VERSION 5.8 ;
BUSBITCHARS "[]" ;
DIVIDERCHAR "/" ;
UNITS
    DATABASE MICRONS 1000 ;
END UNITS

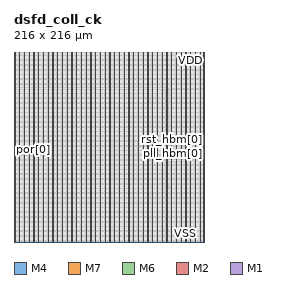
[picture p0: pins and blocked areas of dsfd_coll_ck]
MACRO dsfd_coll_ck
  FOREIGN dsfd_coll_ck 0 0 ;
  CLASS BLOCK ;
  SIZE 216 BY 216 ;
  PIN pll_hbm[0]
    DIRECTION OUTPUT ;
    USE SIGNAL ;
    PORT
      LAYER M4 ;
        RECT  215.808 100.8 216 100.824 ;
    END
  END pll_hbm[0]
  PIN pll_serial[0]
    DIRECTION OUTPUT ;
    USE SIGNAL ;
    PORT
      LAYER M4 ;
        RECT  215.808 98.4 216 98.424 ;
    END
  END pll_serial[0]
  PIN pll_stream[0]
    DIRECTION OUTPUT ;
    USE SIGNAL ;
    PORT
      LAYER M4 ;
        RECT  215.808 96 216 96.024 ;
    END
  END pll_stream[0]
  PIN por[0]
    DIRECTION INPUT ;
    USE SIGNAL ;
    PORT
      LAYER M4 ;
        RECT  0 105.6 0.192 105.624 ;
    END
  END por[0]
  PIN refclk[0]
    DIRECTION INPUT ;
    USE SIGNAL ;
    PORT
      LAYER M4 ;
        RECT  0 100.8 0.192 100.824 ;
    END
  END refclk[0]
  PIN rst_hbm[0]
    DIRECTION OUTPUT ;
    USE SIGNAL ;
    PORT
      LAYER M4 ;
        RECT  215.808 108 216 108.024 ;
    END
  END rst_hbm[0]
  PIN rst_serial[0]
    DIRECTION OUTPUT ;
    USE SIGNAL ;
    PORT
      LAYER M4 ;
        RECT  215.808 105.6 216 105.624 ;
    END
  END rst_serial[0]
  PIN rst_stream[0]
    DIRECTION OUTPUT ;
    USE SIGNAL ;
    PORT
      LAYER M4 ;
        RECT  215.808 103.2 216 103.224 ;
    END
  END rst_stream[0]
  PIN VDD
    DIRECTION INOUT ;
    USE POWER ;
    PORT
      LAYER M7 ;
        RECT  211.456 0.531 211.744 215.469 ;
        RECT  200.656 0.531 200.944 215.469 ;
        RECT  189.856 0.531 190.144 215.469 ;
        RECT  179.056 0.531 179.344 215.469 ;
        RECT  168.256 0.531 168.544 215.469 ;
        RECT  157.456 0.531 157.744 215.469 ;
        RECT  146.656 0.531 146.944 215.469 ;
        RECT  135.856 0.531 136.144 215.469 ;
        RECT  125.056 0.531 125.344 215.469 ;
        RECT  114.256 0.531 114.544 215.469 ;
        RECT  103.456 0.531 103.744 215.469 ;
        RECT  92.656 0.531 92.944 215.469 ;
        RECT  81.856 0.531 82.144 215.469 ;
        RECT  71.056 0.531 71.344 215.469 ;
        RECT  60.256 0.531 60.544 215.469 ;
        RECT  49.456 0.531 49.744 215.469 ;
        RECT  38.656 0.531 38.944 215.469 ;
        RECT  27.856 0.531 28.144 215.469 ;
        RECT  17.056 0.531 17.344 215.469 ;
        RECT  6.256 0.531 6.544 215.469 ;
      LAYER M6 ;
        RECT  215.968 212.172 216 212.46 ;
        RECT  0 212.172 0.032 212.46 ;
        RECT  215.968 206.772 216 207.06 ;
        RECT  0 206.772 0.032 207.06 ;
        RECT  215.968 201.372 216 201.66 ;
        RECT  0 201.372 0.032 201.66 ;
        RECT  215.968 195.972 216 196.26 ;
        RECT  0 195.972 0.032 196.26 ;
        RECT  215.968 190.572 216 190.86 ;
        RECT  0 190.572 0.032 190.86 ;
        RECT  215.968 185.172 216 185.46 ;
        RECT  0 185.172 0.032 185.46 ;
        RECT  215.968 179.772 216 180.06 ;
        RECT  0 179.772 0.032 180.06 ;
        RECT  215.968 174.372 216 174.66 ;
        RECT  0 174.372 0.032 174.66 ;
        RECT  215.968 168.972 216 169.26 ;
        RECT  0 168.972 0.032 169.26 ;
        RECT  215.968 163.572 216 163.86 ;
        RECT  0 163.572 0.032 163.86 ;
        RECT  215.968 158.172 216 158.46 ;
        RECT  0 158.172 0.032 158.46 ;
        RECT  215.968 152.772 216 153.06 ;
        RECT  0 152.772 0.032 153.06 ;
        RECT  215.968 147.372 216 147.66 ;
        RECT  0 147.372 0.032 147.66 ;
        RECT  215.968 141.972 216 142.26 ;
        RECT  0 141.972 0.032 142.26 ;
        RECT  215.968 136.572 216 136.86 ;
        RECT  0 136.572 0.032 136.86 ;
        RECT  215.968 131.172 216 131.46 ;
        RECT  0 131.172 0.032 131.46 ;
        RECT  215.968 125.772 216 126.06 ;
        RECT  0 125.772 0.032 126.06 ;
        RECT  215.968 120.372 216 120.66 ;
        RECT  0 120.372 0.032 120.66 ;
        RECT  215.968 114.972 216 115.26 ;
        RECT  0 114.972 0.032 115.26 ;
        RECT  215.968 109.572 216 109.86 ;
        RECT  0 109.572 0.032 109.86 ;
        RECT  215.968 104.172 216 104.46 ;
        RECT  0 104.172 0.032 104.46 ;
        RECT  215.968 98.772 216 99.06 ;
        RECT  0 98.772 0.032 99.06 ;
        RECT  215.968 93.372 216 93.66 ;
        RECT  0 93.372 0.032 93.66 ;
        RECT  215.968 87.972 216 88.26 ;
        RECT  0 87.972 0.032 88.26 ;
        RECT  215.968 82.572 216 82.86 ;
        RECT  0 82.572 0.032 82.86 ;
        RECT  215.968 77.172 216 77.46 ;
        RECT  0 77.172 0.032 77.46 ;
        RECT  215.968 71.772 216 72.06 ;
        RECT  0 71.772 0.032 72.06 ;
        RECT  215.968 66.372 216 66.66 ;
        RECT  0 66.372 0.032 66.66 ;
        RECT  215.968 60.972 216 61.26 ;
        RECT  0 60.972 0.032 61.26 ;
        RECT  215.968 55.572 216 55.86 ;
        RECT  0 55.572 0.032 55.86 ;
        RECT  215.968 50.172 216 50.46 ;
        RECT  0 50.172 0.032 50.46 ;
        RECT  215.968 44.772 216 45.06 ;
        RECT  0 44.772 0.032 45.06 ;
        RECT  215.968 39.372 216 39.66 ;
        RECT  0 39.372 0.032 39.66 ;
        RECT  215.968 33.972 216 34.26 ;
        RECT  0 33.972 0.032 34.26 ;
        RECT  215.968 28.572 216 28.86 ;
        RECT  0 28.572 0.032 28.86 ;
        RECT  215.968 23.172 216 23.46 ;
        RECT  0 23.172 0.032 23.46 ;
        RECT  215.968 17.772 216 18.06 ;
        RECT  0 17.772 0.032 18.06 ;
        RECT  215.968 12.372 216 12.66 ;
        RECT  0 12.372 0.032 12.66 ;
        RECT  215.968 6.972 216 7.26 ;
        RECT  0 6.972 0.032 7.26 ;
        RECT  215.968 1.572 216 1.86 ;
        RECT  0 1.572 0.032 1.86 ;
      LAYER M2 ;
        RECT  215.982 175.221 216 175.239 ;
        RECT  215.982 174.681 216 174.699 ;
        RECT  215.982 174.141 216 174.159 ;
        RECT  215.982 173.601 216 173.619 ;
        RECT  215.982 173.061 216 173.079 ;
        RECT  215.982 172.521 216 172.539 ;
        RECT  215.982 171.981 216 171.999 ;
        RECT  215.982 171.441 216 171.459 ;
        RECT  215.982 170.901 216 170.919 ;
        RECT  215.982 170.361 216 170.379 ;
        RECT  215.982 169.821 216 169.839 ;
        RECT  215.982 169.281 216 169.299 ;
        RECT  215.982 168.741 216 168.759 ;
        RECT  215.982 168.201 216 168.219 ;
        RECT  215.982 167.661 216 167.679 ;
        RECT  215.982 167.121 216 167.139 ;
        RECT  215.982 166.581 216 166.599 ;
        RECT  215.982 166.041 216 166.059 ;
        RECT  215.982 165.501 216 165.519 ;
        RECT  215.982 164.961 216 164.979 ;
        RECT  215.982 164.421 216 164.439 ;
        RECT  215.982 163.881 216 163.899 ;
        RECT  215.982 163.341 216 163.359 ;
        RECT  215.982 162.801 216 162.819 ;
        RECT  215.982 162.261 216 162.279 ;
        RECT  215.982 161.721 216 161.739 ;
        RECT  215.982 161.181 216 161.199 ;
        RECT  215.982 160.641 216 160.659 ;
        RECT  215.982 160.101 216 160.119 ;
        RECT  215.982 159.561 216 159.579 ;
        RECT  215.982 159.021 216 159.039 ;
        RECT  215.982 158.481 216 158.499 ;
        RECT  215.982 157.941 216 157.959 ;
        RECT  215.982 157.401 216 157.419 ;
        RECT  215.982 156.861 216 156.879 ;
        RECT  215.982 156.321 216 156.339 ;
        RECT  215.982 155.781 216 155.799 ;
        RECT  215.982 155.241 216 155.259 ;
        RECT  215.982 154.701 216 154.719 ;
        RECT  215.982 154.161 216 154.179 ;
        RECT  215.982 153.621 216 153.639 ;
        RECT  215.982 153.081 216 153.099 ;
        RECT  215.982 152.541 216 152.559 ;
        RECT  215.982 152.001 216 152.019 ;
        RECT  215.982 151.461 216 151.479 ;
        RECT  215.982 150.921 216 150.939 ;
        RECT  215.982 150.381 216 150.399 ;
        RECT  215.982 149.841 216 149.859 ;
        RECT  215.982 149.301 216 149.319 ;
        RECT  215.982 148.761 216 148.779 ;
        RECT  215.982 148.221 216 148.239 ;
        RECT  215.982 147.681 216 147.699 ;
        RECT  215.982 147.141 216 147.159 ;
        RECT  215.982 146.601 216 146.619 ;
        RECT  215.982 146.061 216 146.079 ;
        RECT  215.982 145.521 216 145.539 ;
        RECT  215.982 144.981 216 144.999 ;
        RECT  215.982 144.441 216 144.459 ;
        RECT  215.982 143.901 216 143.919 ;
        RECT  215.982 143.361 216 143.379 ;
        RECT  215.982 142.821 216 142.839 ;
        RECT  215.982 142.281 216 142.299 ;
        RECT  215.982 141.741 216 141.759 ;
        RECT  215.982 141.201 216 141.219 ;
        RECT  215.982 140.661 216 140.679 ;
        RECT  215.982 140.121 216 140.139 ;
        RECT  215.982 139.581 216 139.599 ;
        RECT  215.982 139.041 216 139.059 ;
        RECT  215.982 138.501 216 138.519 ;
        RECT  215.982 137.961 216 137.979 ;
        RECT  215.982 137.421 216 137.439 ;
        RECT  215.982 136.881 216 136.899 ;
        RECT  215.982 136.341 216 136.359 ;
        RECT  215.982 135.801 216 135.819 ;
        RECT  215.982 135.261 216 135.279 ;
        RECT  215.982 134.721 216 134.739 ;
        RECT  215.982 134.181 216 134.199 ;
        RECT  215.982 133.641 216 133.659 ;
        RECT  215.982 133.101 216 133.119 ;
        RECT  215.982 132.561 216 132.579 ;
        RECT  215.982 132.021 216 132.039 ;
        RECT  215.982 131.481 216 131.499 ;
        RECT  215.982 130.941 216 130.959 ;
        RECT  215.982 130.401 216 130.419 ;
        RECT  215.982 129.861 216 129.879 ;
        RECT  215.982 129.321 216 129.339 ;
        RECT  215.982 128.781 216 128.799 ;
        RECT  215.982 128.241 216 128.259 ;
        RECT  215.982 127.701 216 127.719 ;
        RECT  215.982 127.161 216 127.179 ;
        RECT  215.982 126.621 216 126.639 ;
        RECT  215.982 126.081 216 126.099 ;
        RECT  215.982 125.541 216 125.559 ;
        RECT  215.982 125.001 216 125.019 ;
        RECT  215.982 124.461 216 124.479 ;
        RECT  215.982 123.921 216 123.939 ;
        RECT  215.982 123.381 216 123.399 ;
        RECT  215.982 122.841 216 122.859 ;
        RECT  215.982 122.301 216 122.319 ;
        RECT  215.982 121.761 216 121.779 ;
        RECT  215.982 121.221 216 121.239 ;
        RECT  215.982 120.681 216 120.699 ;
        RECT  215.982 120.141 216 120.159 ;
        RECT  215.982 119.601 216 119.619 ;
        RECT  215.982 119.061 216 119.079 ;
        RECT  215.982 118.521 216 118.539 ;
        RECT  215.982 117.981 216 117.999 ;
        RECT  215.982 117.441 216 117.459 ;
        RECT  215.982 116.901 216 116.919 ;
        RECT  215.982 116.361 216 116.379 ;
        RECT  215.982 115.821 216 115.839 ;
        RECT  215.982 115.281 216 115.299 ;
        RECT  215.982 114.741 216 114.759 ;
        RECT  215.982 114.201 216 114.219 ;
        RECT  215.982 113.661 216 113.679 ;
        RECT  215.982 113.121 216 113.139 ;
        RECT  215.982 112.581 216 112.599 ;
        RECT  215.982 112.041 216 112.059 ;
        RECT  215.982 111.501 216 111.519 ;
        RECT  215.982 110.961 216 110.979 ;
        RECT  215.982 110.421 216 110.439 ;
        RECT  215.982 109.881 216 109.899 ;
        RECT  215.982 109.341 216 109.359 ;
        RECT  215.982 108.801 216 108.819 ;
        RECT  215.982 108.261 216 108.279 ;
        RECT  215.982 107.721 216 107.739 ;
        RECT  215.982 107.181 216 107.199 ;
        RECT  215.982 106.641 216 106.659 ;
        RECT  215.982 106.101 216 106.119 ;
        RECT  215.982 105.561 216 105.579 ;
        RECT  215.982 105.021 216 105.039 ;
        RECT  215.982 104.481 216 104.499 ;
        RECT  215.982 103.941 216 103.959 ;
        RECT  215.982 103.401 216 103.419 ;
        RECT  215.982 102.861 216 102.879 ;
        RECT  215.982 102.321 216 102.339 ;
        RECT  215.982 101.781 216 101.799 ;
        RECT  215.982 101.241 216 101.259 ;
        RECT  215.982 100.701 216 100.719 ;
        RECT  215.982 100.161 216 100.179 ;
        RECT  215.982 99.621 216 99.639 ;
        RECT  215.982 99.081 216 99.099 ;
        RECT  215.982 98.541 216 98.559 ;
        RECT  215.982 98.001 216 98.019 ;
        RECT  215.982 97.461 216 97.479 ;
        RECT  215.982 96.921 216 96.939 ;
        RECT  215.982 96.381 216 96.399 ;
        RECT  215.982 95.841 216 95.859 ;
        RECT  215.982 95.301 216 95.319 ;
        RECT  215.982 94.761 216 94.779 ;
        RECT  215.982 94.221 216 94.239 ;
        RECT  215.982 93.681 216 93.699 ;
        RECT  215.982 93.141 216 93.159 ;
        RECT  215.982 92.601 216 92.619 ;
        RECT  215.982 92.061 216 92.079 ;
        RECT  215.982 91.521 216 91.539 ;
        RECT  215.982 90.981 216 90.999 ;
        RECT  215.982 90.441 216 90.459 ;
        RECT  215.982 89.901 216 89.919 ;
        RECT  215.982 89.361 216 89.379 ;
        RECT  215.982 88.821 216 88.839 ;
        RECT  215.982 88.281 216 88.299 ;
        RECT  215.982 87.741 216 87.759 ;
        RECT  215.982 87.201 216 87.219 ;
        RECT  215.982 86.661 216 86.679 ;
        RECT  215.982 86.121 216 86.139 ;
        RECT  215.982 85.581 216 85.599 ;
        RECT  215.982 85.041 216 85.059 ;
        RECT  215.982 84.501 216 84.519 ;
        RECT  215.982 83.961 216 83.979 ;
        RECT  215.982 83.421 216 83.439 ;
        RECT  215.982 82.881 216 82.899 ;
        RECT  215.982 82.341 216 82.359 ;
        RECT  215.982 81.801 216 81.819 ;
        RECT  215.982 81.261 216 81.279 ;
        RECT  215.982 80.721 216 80.739 ;
        RECT  215.982 80.181 216 80.199 ;
        RECT  215.982 79.641 216 79.659 ;
        RECT  215.982 79.101 216 79.119 ;
        RECT  215.982 78.561 216 78.579 ;
        RECT  215.982 78.021 216 78.039 ;
        RECT  215.982 77.481 216 77.499 ;
        RECT  215.982 76.941 216 76.959 ;
        RECT  215.982 76.401 216 76.419 ;
        RECT  215.982 75.861 216 75.879 ;
        RECT  215.982 75.321 216 75.339 ;
        RECT  215.982 74.781 216 74.799 ;
        RECT  215.982 74.241 216 74.259 ;
        RECT  215.982 73.701 216 73.719 ;
        RECT  215.982 73.161 216 73.179 ;
        RECT  215.982 72.621 216 72.639 ;
        RECT  215.982 72.081 216 72.099 ;
        RECT  215.982 71.541 216 71.559 ;
        RECT  215.982 71.001 216 71.019 ;
        RECT  215.982 70.461 216 70.479 ;
        RECT  215.982 69.921 216 69.939 ;
        RECT  215.982 69.381 216 69.399 ;
        RECT  215.982 68.841 216 68.859 ;
        RECT  215.982 68.301 216 68.319 ;
        RECT  215.982 67.761 216 67.779 ;
        RECT  215.982 67.221 216 67.239 ;
        RECT  215.982 66.681 216 66.699 ;
        RECT  215.982 66.141 216 66.159 ;
        RECT  215.982 65.601 216 65.619 ;
        RECT  215.982 65.061 216 65.079 ;
        RECT  215.982 64.521 216 64.539 ;
        RECT  215.982 63.981 216 63.999 ;
        RECT  215.982 63.441 216 63.459 ;
        RECT  215.982 62.901 216 62.919 ;
        RECT  215.982 62.361 216 62.379 ;
        RECT  215.982 61.821 216 61.839 ;
        RECT  215.982 61.281 216 61.299 ;
        RECT  215.982 60.741 216 60.759 ;
        RECT  215.982 60.201 216 60.219 ;
        RECT  215.982 59.661 216 59.679 ;
        RECT  215.982 59.121 216 59.139 ;
        RECT  215.982 58.581 216 58.599 ;
        RECT  215.982 58.041 216 58.059 ;
        RECT  215.982 57.501 216 57.519 ;
        RECT  215.982 56.961 216 56.979 ;
        RECT  215.982 56.421 216 56.439 ;
        RECT  215.982 55.881 216 55.899 ;
        RECT  215.982 55.341 216 55.359 ;
        RECT  215.982 54.801 216 54.819 ;
        RECT  215.982 54.261 216 54.279 ;
        RECT  215.982 53.721 216 53.739 ;
        RECT  215.982 53.181 216 53.199 ;
        RECT  215.982 52.641 216 52.659 ;
        RECT  215.982 52.101 216 52.119 ;
        RECT  215.982 51.561 216 51.579 ;
        RECT  215.982 51.021 216 51.039 ;
        RECT  215.982 50.481 216 50.499 ;
        RECT  215.982 49.941 216 49.959 ;
        RECT  215.982 49.401 216 49.419 ;
        RECT  215.982 48.861 216 48.879 ;
        RECT  215.982 48.321 216 48.339 ;
        RECT  215.982 47.781 216 47.799 ;
        RECT  215.982 47.241 216 47.259 ;
        RECT  215.982 46.701 216 46.719 ;
        RECT  215.982 46.161 216 46.179 ;
        RECT  215.982 45.621 216 45.639 ;
        RECT  215.982 45.081 216 45.099 ;
        RECT  215.982 44.541 216 44.559 ;
        RECT  215.982 44.001 216 44.019 ;
        RECT  215.982 43.461 216 43.479 ;
        RECT  215.982 42.921 216 42.939 ;
        RECT  215.982 42.381 216 42.399 ;
        RECT  215.982 41.841 216 41.859 ;
        RECT  215.982 41.301 216 41.319 ;
        RECT  215.982 40.761 216 40.779 ;
        RECT  215.982 40.221 216 40.239 ;
        RECT  215.982 39.681 216 39.699 ;
        RECT  215.982 39.141 216 39.159 ;
        RECT  215.982 38.601 216 38.619 ;
        RECT  215.982 38.061 216 38.079 ;
        RECT  215.982 37.521 216 37.539 ;
        RECT  215.982 36.981 216 36.999 ;
        RECT  215.982 36.441 216 36.459 ;
        RECT  215.982 35.901 216 35.919 ;
        RECT  215.982 35.361 216 35.379 ;
        RECT  215.982 34.821 216 34.839 ;
        RECT  215.982 34.281 216 34.299 ;
        RECT  215.982 33.741 216 33.759 ;
        RECT  215.982 33.201 216 33.219 ;
        RECT  215.982 32.661 216 32.679 ;
        RECT  215.982 32.121 216 32.139 ;
        RECT  215.982 31.581 216 31.599 ;
        RECT  215.982 31.041 216 31.059 ;
        RECT  215.982 30.501 216 30.519 ;
        RECT  215.982 29.961 216 29.979 ;
        RECT  215.982 29.421 216 29.439 ;
        RECT  215.982 28.881 216 28.899 ;
        RECT  215.982 28.341 216 28.359 ;
        RECT  215.982 27.801 216 27.819 ;
        RECT  215.982 27.261 216 27.279 ;
        RECT  215.982 26.721 216 26.739 ;
        RECT  215.982 26.181 216 26.199 ;
        RECT  215.982 25.641 216 25.659 ;
        RECT  215.982 25.101 216 25.119 ;
        RECT  215.982 24.561 216 24.579 ;
        RECT  215.982 24.021 216 24.039 ;
        RECT  215.982 23.481 216 23.499 ;
        RECT  215.982 22.941 216 22.959 ;
        RECT  215.982 22.401 216 22.419 ;
        RECT  215.982 21.861 216 21.879 ;
        RECT  215.982 21.321 216 21.339 ;
        RECT  215.982 20.781 216 20.799 ;
        RECT  215.982 20.241 216 20.259 ;
        RECT  215.982 19.701 216 19.719 ;
        RECT  215.982 19.161 216 19.179 ;
        RECT  215.982 18.621 216 18.639 ;
        RECT  215.982 18.081 216 18.099 ;
        RECT  215.982 17.541 216 17.559 ;
        RECT  215.982 17.001 216 17.019 ;
        RECT  215.982 16.461 216 16.479 ;
        RECT  215.982 15.921 216 15.939 ;
        RECT  215.982 15.381 216 15.399 ;
        RECT  215.982 14.841 216 14.859 ;
        RECT  215.982 14.301 216 14.319 ;
        RECT  215.982 13.761 216 13.779 ;
        RECT  215.982 13.221 216 13.239 ;
        RECT  215.982 12.681 216 12.699 ;
        RECT  215.982 12.141 216 12.159 ;
        RECT  215.982 11.601 216 11.619 ;
        RECT  215.982 11.061 216 11.079 ;
        RECT  215.982 10.521 216 10.539 ;
        RECT  215.982 9.981 216 9.999 ;
        RECT  215.982 9.441 216 9.459 ;
        RECT  215.982 8.901 216 8.919 ;
        RECT  215.982 8.361 216 8.379 ;
        RECT  215.982 7.821 216 7.839 ;
        RECT  215.982 7.281 216 7.299 ;
        RECT  215.982 6.741 216 6.759 ;
        RECT  215.982 6.201 216 6.219 ;
        RECT  215.982 5.661 216 5.679 ;
        RECT  215.982 5.121 216 5.139 ;
        RECT  215.982 4.581 216 4.599 ;
        RECT  215.982 4.041 216 4.059 ;
        RECT  215.982 3.501 216 3.519 ;
        RECT  215.982 2.961 216 2.979 ;
        RECT  215.982 2.421 216 2.439 ;
        RECT  215.982 1.881 216 1.899 ;
        RECT  215.982 1.341 216 1.359 ;
        RECT  215.982 0.801 216 0.819 ;
        RECT  215.982 215.181 216 215.199 ;
        RECT  0 215.181 0.018 215.199 ;
        RECT  215.982 214.641 216 214.659 ;
        RECT  0 214.641 0.018 214.659 ;
        RECT  215.982 214.101 216 214.119 ;
        RECT  0 214.101 0.018 214.119 ;
        RECT  215.982 213.561 216 213.579 ;
        RECT  0 213.561 0.018 213.579 ;
        RECT  215.982 213.021 216 213.039 ;
        RECT  0 213.021 0.018 213.039 ;
        RECT  215.982 212.481 216 212.499 ;
        RECT  0 212.481 0.018 212.499 ;
        RECT  215.982 211.941 216 211.959 ;
        RECT  0 211.941 0.018 211.959 ;
        RECT  215.982 211.401 216 211.419 ;
        RECT  0 211.401 0.018 211.419 ;
        RECT  215.982 210.861 216 210.879 ;
        RECT  0 210.861 0.018 210.879 ;
        RECT  215.982 210.321 216 210.339 ;
        RECT  0 210.321 0.018 210.339 ;
        RECT  215.982 209.781 216 209.799 ;
        RECT  0 209.781 0.018 209.799 ;
        RECT  215.982 209.241 216 209.259 ;
        RECT  0 209.241 0.018 209.259 ;
        RECT  215.982 208.701 216 208.719 ;
        RECT  0 208.701 0.018 208.719 ;
        RECT  215.982 208.161 216 208.179 ;
        RECT  0 208.161 0.018 208.179 ;
        RECT  215.982 207.621 216 207.639 ;
        RECT  0 207.621 0.018 207.639 ;
        RECT  215.982 207.081 216 207.099 ;
        RECT  0 207.081 0.018 207.099 ;
        RECT  215.982 206.541 216 206.559 ;
        RECT  0 206.541 0.018 206.559 ;
        RECT  215.982 206.001 216 206.019 ;
        RECT  0 206.001 0.018 206.019 ;
        RECT  215.982 205.461 216 205.479 ;
        RECT  0 205.461 0.018 205.479 ;
        RECT  215.982 204.921 216 204.939 ;
        RECT  0 204.921 0.018 204.939 ;
        RECT  215.982 204.381 216 204.399 ;
        RECT  0 204.381 0.018 204.399 ;
        RECT  215.982 203.841 216 203.859 ;
        RECT  0 203.841 0.018 203.859 ;
        RECT  215.982 203.301 216 203.319 ;
        RECT  0 203.301 0.018 203.319 ;
        RECT  215.982 202.761 216 202.779 ;
        RECT  0 202.761 0.018 202.779 ;
        RECT  215.982 202.221 216 202.239 ;
        RECT  0 202.221 0.018 202.239 ;
        RECT  215.982 201.681 216 201.699 ;
        RECT  0 201.681 0.018 201.699 ;
        RECT  215.982 201.141 216 201.159 ;
        RECT  0 201.141 0.018 201.159 ;
        RECT  215.982 200.601 216 200.619 ;
        RECT  0 200.601 0.018 200.619 ;
        RECT  215.982 200.061 216 200.079 ;
        RECT  0 200.061 0.018 200.079 ;
        RECT  215.982 199.521 216 199.539 ;
        RECT  0 199.521 0.018 199.539 ;
        RECT  215.982 198.981 216 198.999 ;
        RECT  0 198.981 0.018 198.999 ;
        RECT  215.982 198.441 216 198.459 ;
        RECT  0 198.441 0.018 198.459 ;
        RECT  215.982 197.901 216 197.919 ;
        RECT  0 197.901 0.018 197.919 ;
        RECT  215.982 197.361 216 197.379 ;
        RECT  0 197.361 0.018 197.379 ;
        RECT  215.982 196.821 216 196.839 ;
        RECT  0 196.821 0.018 196.839 ;
        RECT  215.982 196.281 216 196.299 ;
        RECT  0 196.281 0.018 196.299 ;
        RECT  215.982 195.741 216 195.759 ;
        RECT  0 195.741 0.018 195.759 ;
        RECT  215.982 195.201 216 195.219 ;
        RECT  0 195.201 0.018 195.219 ;
        RECT  215.982 194.661 216 194.679 ;
        RECT  0 194.661 0.018 194.679 ;
        RECT  215.982 194.121 216 194.139 ;
        RECT  0 194.121 0.018 194.139 ;
        RECT  215.982 193.581 216 193.599 ;
        RECT  0 193.581 0.018 193.599 ;
        RECT  215.982 193.041 216 193.059 ;
        RECT  0 193.041 0.018 193.059 ;
        RECT  215.982 192.501 216 192.519 ;
        RECT  0 192.501 0.018 192.519 ;
        RECT  215.982 191.961 216 191.979 ;
        RECT  0 191.961 0.018 191.979 ;
        RECT  215.982 191.421 216 191.439 ;
        RECT  0 191.421 0.018 191.439 ;
        RECT  215.982 190.881 216 190.899 ;
        RECT  0 190.881 0.018 190.899 ;
        RECT  215.982 190.341 216 190.359 ;
        RECT  0 190.341 0.018 190.359 ;
        RECT  215.982 189.801 216 189.819 ;
        RECT  0 189.801 0.018 189.819 ;
        RECT  215.982 189.261 216 189.279 ;
        RECT  0 189.261 0.018 189.279 ;
        RECT  215.982 188.721 216 188.739 ;
        RECT  0 188.721 0.018 188.739 ;
        RECT  215.982 188.181 216 188.199 ;
        RECT  0 188.181 0.018 188.199 ;
        RECT  215.982 187.641 216 187.659 ;
        RECT  0 187.641 0.018 187.659 ;
        RECT  215.982 187.101 216 187.119 ;
        RECT  0 187.101 0.018 187.119 ;
        RECT  215.982 186.561 216 186.579 ;
        RECT  0 186.561 0.018 186.579 ;
        RECT  215.982 186.021 216 186.039 ;
        RECT  0 186.021 0.018 186.039 ;
        RECT  215.982 185.481 216 185.499 ;
        RECT  0 185.481 0.018 185.499 ;
        RECT  215.982 184.941 216 184.959 ;
        RECT  0 184.941 0.018 184.959 ;
        RECT  215.982 184.401 216 184.419 ;
        RECT  0 184.401 0.018 184.419 ;
        RECT  215.982 183.861 216 183.879 ;
        RECT  0 183.861 0.018 183.879 ;
        RECT  215.982 183.321 216 183.339 ;
        RECT  0 183.321 0.018 183.339 ;
        RECT  215.982 182.781 216 182.799 ;
        RECT  0 182.781 0.018 182.799 ;
        RECT  215.982 182.241 216 182.259 ;
        RECT  0 182.241 0.018 182.259 ;
        RECT  215.982 181.701 216 181.719 ;
        RECT  0 181.701 0.018 181.719 ;
        RECT  215.982 181.161 216 181.179 ;
        RECT  0 181.161 0.018 181.179 ;
        RECT  215.982 180.621 216 180.639 ;
        RECT  0 180.621 0.018 180.639 ;
        RECT  215.982 180.081 216 180.099 ;
        RECT  0 180.081 0.018 180.099 ;
        RECT  215.982 179.541 216 179.559 ;
        RECT  0 179.541 0.018 179.559 ;
        RECT  215.982 179.001 216 179.019 ;
        RECT  0 179.001 0.018 179.019 ;
        RECT  215.982 178.461 216 178.479 ;
        RECT  0 178.461 0.018 178.479 ;
        RECT  215.982 177.921 216 177.939 ;
        RECT  0 177.921 0.018 177.939 ;
        RECT  215.982 177.381 216 177.399 ;
        RECT  0 177.381 0.018 177.399 ;
        RECT  215.982 176.841 216 176.859 ;
        RECT  0 176.841 0.018 176.859 ;
        RECT  215.982 176.301 216 176.319 ;
        RECT  0 176.301 0.018 176.319 ;
        RECT  215.982 175.761 216 175.779 ;
        RECT  0 175.761 0.018 175.779 ;
      LAYER M1 ;
        RECT  215.982 175.221 216 175.239 ;
        RECT  215.982 174.681 216 174.699 ;
        RECT  215.982 174.141 216 174.159 ;
        RECT  215.982 173.601 216 173.619 ;
        RECT  215.982 173.061 216 173.079 ;
        RECT  215.982 172.521 216 172.539 ;
        RECT  215.982 171.981 216 171.999 ;
        RECT  215.982 171.441 216 171.459 ;
        RECT  215.982 170.901 216 170.919 ;
        RECT  215.982 170.361 216 170.379 ;
        RECT  215.982 169.821 216 169.839 ;
        RECT  215.982 169.281 216 169.299 ;
        RECT  215.982 168.741 216 168.759 ;
        RECT  215.982 168.201 216 168.219 ;
        RECT  215.982 167.661 216 167.679 ;
        RECT  215.982 167.121 216 167.139 ;
        RECT  215.982 166.581 216 166.599 ;
        RECT  215.982 166.041 216 166.059 ;
        RECT  215.982 165.501 216 165.519 ;
        RECT  215.982 164.961 216 164.979 ;
        RECT  215.982 164.421 216 164.439 ;
        RECT  215.982 163.881 216 163.899 ;
        RECT  215.982 163.341 216 163.359 ;
        RECT  215.982 162.801 216 162.819 ;
        RECT  215.982 162.261 216 162.279 ;
        RECT  215.982 161.721 216 161.739 ;
        RECT  215.982 161.181 216 161.199 ;
        RECT  215.982 160.641 216 160.659 ;
        RECT  215.982 160.101 216 160.119 ;
        RECT  215.982 159.561 216 159.579 ;
        RECT  215.982 159.021 216 159.039 ;
        RECT  215.982 158.481 216 158.499 ;
        RECT  215.982 157.941 216 157.959 ;
        RECT  215.982 157.401 216 157.419 ;
        RECT  215.982 156.861 216 156.879 ;
        RECT  215.982 156.321 216 156.339 ;
        RECT  215.982 155.781 216 155.799 ;
        RECT  215.982 155.241 216 155.259 ;
        RECT  215.982 154.701 216 154.719 ;
        RECT  215.982 154.161 216 154.179 ;
        RECT  215.982 153.621 216 153.639 ;
        RECT  215.982 153.081 216 153.099 ;
        RECT  215.982 152.541 216 152.559 ;
        RECT  215.982 152.001 216 152.019 ;
        RECT  215.982 151.461 216 151.479 ;
        RECT  215.982 150.921 216 150.939 ;
        RECT  215.982 150.381 216 150.399 ;
        RECT  215.982 149.841 216 149.859 ;
        RECT  215.982 149.301 216 149.319 ;
        RECT  215.982 148.761 216 148.779 ;
        RECT  215.982 148.221 216 148.239 ;
        RECT  215.982 147.681 216 147.699 ;
        RECT  215.982 147.141 216 147.159 ;
        RECT  215.982 146.601 216 146.619 ;
        RECT  215.982 146.061 216 146.079 ;
        RECT  215.982 145.521 216 145.539 ;
        RECT  215.982 144.981 216 144.999 ;
        RECT  215.982 144.441 216 144.459 ;
        RECT  215.982 143.901 216 143.919 ;
        RECT  215.982 143.361 216 143.379 ;
        RECT  215.982 142.821 216 142.839 ;
        RECT  215.982 142.281 216 142.299 ;
        RECT  215.982 141.741 216 141.759 ;
        RECT  215.982 141.201 216 141.219 ;
        RECT  215.982 140.661 216 140.679 ;
        RECT  215.982 140.121 216 140.139 ;
        RECT  215.982 139.581 216 139.599 ;
        RECT  215.982 139.041 216 139.059 ;
        RECT  215.982 138.501 216 138.519 ;
        RECT  215.982 137.961 216 137.979 ;
        RECT  215.982 137.421 216 137.439 ;
        RECT  215.982 136.881 216 136.899 ;
        RECT  215.982 136.341 216 136.359 ;
        RECT  215.982 135.801 216 135.819 ;
        RECT  215.982 135.261 216 135.279 ;
        RECT  215.982 134.721 216 134.739 ;
        RECT  215.982 134.181 216 134.199 ;
        RECT  215.982 133.641 216 133.659 ;
        RECT  215.982 133.101 216 133.119 ;
        RECT  215.982 132.561 216 132.579 ;
        RECT  215.982 132.021 216 132.039 ;
        RECT  215.982 131.481 216 131.499 ;
        RECT  215.982 130.941 216 130.959 ;
        RECT  215.982 130.401 216 130.419 ;
        RECT  215.982 129.861 216 129.879 ;
        RECT  215.982 129.321 216 129.339 ;
        RECT  215.982 128.781 216 128.799 ;
        RECT  215.982 128.241 216 128.259 ;
        RECT  215.982 127.701 216 127.719 ;
        RECT  215.982 127.161 216 127.179 ;
        RECT  215.982 126.621 216 126.639 ;
        RECT  215.982 126.081 216 126.099 ;
        RECT  215.982 125.541 216 125.559 ;
        RECT  215.982 125.001 216 125.019 ;
        RECT  215.982 124.461 216 124.479 ;
        RECT  215.982 123.921 216 123.939 ;
        RECT  215.982 123.381 216 123.399 ;
        RECT  215.982 122.841 216 122.859 ;
        RECT  215.982 122.301 216 122.319 ;
        RECT  215.982 121.761 216 121.779 ;
        RECT  215.982 121.221 216 121.239 ;
        RECT  215.982 120.681 216 120.699 ;
        RECT  215.982 120.141 216 120.159 ;
        RECT  215.982 119.601 216 119.619 ;
        RECT  215.982 119.061 216 119.079 ;
        RECT  215.982 118.521 216 118.539 ;
        RECT  215.982 117.981 216 117.999 ;
        RECT  215.982 117.441 216 117.459 ;
        RECT  215.982 116.901 216 116.919 ;
        RECT  215.982 116.361 216 116.379 ;
        RECT  215.982 115.821 216 115.839 ;
        RECT  215.982 115.281 216 115.299 ;
        RECT  215.982 114.741 216 114.759 ;
        RECT  215.982 114.201 216 114.219 ;
        RECT  215.982 113.661 216 113.679 ;
        RECT  215.982 113.121 216 113.139 ;
        RECT  215.982 112.581 216 112.599 ;
        RECT  215.982 112.041 216 112.059 ;
        RECT  215.982 111.501 216 111.519 ;
        RECT  215.982 110.961 216 110.979 ;
        RECT  215.982 110.421 216 110.439 ;
        RECT  215.982 109.881 216 109.899 ;
        RECT  215.982 109.341 216 109.359 ;
        RECT  215.982 108.801 216 108.819 ;
        RECT  215.982 108.261 216 108.279 ;
        RECT  215.982 107.721 216 107.739 ;
        RECT  215.982 107.181 216 107.199 ;
        RECT  215.982 106.641 216 106.659 ;
        RECT  215.982 106.101 216 106.119 ;
        RECT  215.982 105.561 216 105.579 ;
        RECT  215.982 105.021 216 105.039 ;
        RECT  215.982 104.481 216 104.499 ;
        RECT  215.982 103.941 216 103.959 ;
        RECT  215.982 103.401 216 103.419 ;
        RECT  215.982 102.861 216 102.879 ;
        RECT  215.982 102.321 216 102.339 ;
        RECT  215.982 101.781 216 101.799 ;
        RECT  215.982 101.241 216 101.259 ;
        RECT  215.982 100.701 216 100.719 ;
        RECT  215.982 100.161 216 100.179 ;
        RECT  215.982 99.621 216 99.639 ;
        RECT  215.982 99.081 216 99.099 ;
        RECT  215.982 98.541 216 98.559 ;
        RECT  215.982 98.001 216 98.019 ;
        RECT  215.982 97.461 216 97.479 ;
        RECT  215.982 96.921 216 96.939 ;
        RECT  215.982 96.381 216 96.399 ;
        RECT  215.982 95.841 216 95.859 ;
        RECT  215.982 95.301 216 95.319 ;
        RECT  215.982 94.761 216 94.779 ;
        RECT  215.982 94.221 216 94.239 ;
        RECT  215.982 93.681 216 93.699 ;
        RECT  215.982 93.141 216 93.159 ;
        RECT  215.982 92.601 216 92.619 ;
        RECT  215.982 92.061 216 92.079 ;
        RECT  215.982 91.521 216 91.539 ;
        RECT  215.982 90.981 216 90.999 ;
        RECT  215.982 90.441 216 90.459 ;
        RECT  215.982 89.901 216 89.919 ;
        RECT  215.982 89.361 216 89.379 ;
        RECT  215.982 88.821 216 88.839 ;
        RECT  215.982 88.281 216 88.299 ;
        RECT  215.982 87.741 216 87.759 ;
        RECT  215.982 87.201 216 87.219 ;
        RECT  215.982 86.661 216 86.679 ;
        RECT  215.982 86.121 216 86.139 ;
        RECT  215.982 85.581 216 85.599 ;
        RECT  215.982 85.041 216 85.059 ;
        RECT  215.982 84.501 216 84.519 ;
        RECT  215.982 83.961 216 83.979 ;
        RECT  215.982 83.421 216 83.439 ;
        RECT  215.982 82.881 216 82.899 ;
        RECT  215.982 82.341 216 82.359 ;
        RECT  215.982 81.801 216 81.819 ;
        RECT  215.982 81.261 216 81.279 ;
        RECT  215.982 80.721 216 80.739 ;
        RECT  215.982 80.181 216 80.199 ;
        RECT  215.982 79.641 216 79.659 ;
        RECT  215.982 79.101 216 79.119 ;
        RECT  215.982 78.561 216 78.579 ;
        RECT  215.982 78.021 216 78.039 ;
        RECT  215.982 77.481 216 77.499 ;
        RECT  215.982 76.941 216 76.959 ;
        RECT  215.982 76.401 216 76.419 ;
        RECT  215.982 75.861 216 75.879 ;
        RECT  215.982 75.321 216 75.339 ;
        RECT  215.982 74.781 216 74.799 ;
        RECT  215.982 74.241 216 74.259 ;
        RECT  215.982 73.701 216 73.719 ;
        RECT  215.982 73.161 216 73.179 ;
        RECT  215.982 72.621 216 72.639 ;
        RECT  215.982 72.081 216 72.099 ;
        RECT  215.982 71.541 216 71.559 ;
        RECT  215.982 71.001 216 71.019 ;
        RECT  215.982 70.461 216 70.479 ;
        RECT  215.982 69.921 216 69.939 ;
        RECT  215.982 69.381 216 69.399 ;
        RECT  215.982 68.841 216 68.859 ;
        RECT  215.982 68.301 216 68.319 ;
        RECT  215.982 67.761 216 67.779 ;
        RECT  215.982 67.221 216 67.239 ;
        RECT  215.982 66.681 216 66.699 ;
        RECT  215.982 66.141 216 66.159 ;
        RECT  215.982 65.601 216 65.619 ;
        RECT  215.982 65.061 216 65.079 ;
        RECT  215.982 64.521 216 64.539 ;
        RECT  215.982 63.981 216 63.999 ;
        RECT  215.982 63.441 216 63.459 ;
        RECT  215.982 62.901 216 62.919 ;
        RECT  215.982 62.361 216 62.379 ;
        RECT  215.982 61.821 216 61.839 ;
        RECT  215.982 61.281 216 61.299 ;
        RECT  215.982 60.741 216 60.759 ;
        RECT  215.982 60.201 216 60.219 ;
        RECT  215.982 59.661 216 59.679 ;
        RECT  215.982 59.121 216 59.139 ;
        RECT  215.982 58.581 216 58.599 ;
        RECT  215.982 58.041 216 58.059 ;
        RECT  215.982 57.501 216 57.519 ;
        RECT  215.982 56.961 216 56.979 ;
        RECT  215.982 56.421 216 56.439 ;
        RECT  215.982 55.881 216 55.899 ;
        RECT  215.982 55.341 216 55.359 ;
        RECT  215.982 54.801 216 54.819 ;
        RECT  215.982 54.261 216 54.279 ;
        RECT  215.982 53.721 216 53.739 ;
        RECT  215.982 53.181 216 53.199 ;
        RECT  215.982 52.641 216 52.659 ;
        RECT  215.982 52.101 216 52.119 ;
        RECT  215.982 51.561 216 51.579 ;
        RECT  215.982 51.021 216 51.039 ;
        RECT  215.982 50.481 216 50.499 ;
        RECT  215.982 49.941 216 49.959 ;
        RECT  215.982 49.401 216 49.419 ;
        RECT  215.982 48.861 216 48.879 ;
        RECT  215.982 48.321 216 48.339 ;
        RECT  215.982 47.781 216 47.799 ;
        RECT  215.982 47.241 216 47.259 ;
        RECT  215.982 46.701 216 46.719 ;
        RECT  215.982 46.161 216 46.179 ;
        RECT  215.982 45.621 216 45.639 ;
        RECT  215.982 45.081 216 45.099 ;
        RECT  215.982 44.541 216 44.559 ;
        RECT  215.982 44.001 216 44.019 ;
        RECT  215.982 43.461 216 43.479 ;
        RECT  215.982 42.921 216 42.939 ;
        RECT  215.982 42.381 216 42.399 ;
        RECT  215.982 41.841 216 41.859 ;
        RECT  215.982 41.301 216 41.319 ;
        RECT  215.982 40.761 216 40.779 ;
        RECT  215.982 40.221 216 40.239 ;
        RECT  215.982 39.681 216 39.699 ;
        RECT  215.982 39.141 216 39.159 ;
        RECT  215.982 38.601 216 38.619 ;
        RECT  215.982 38.061 216 38.079 ;
        RECT  215.982 37.521 216 37.539 ;
        RECT  215.982 36.981 216 36.999 ;
        RECT  215.982 36.441 216 36.459 ;
        RECT  215.982 35.901 216 35.919 ;
        RECT  215.982 35.361 216 35.379 ;
        RECT  215.982 34.821 216 34.839 ;
        RECT  215.982 34.281 216 34.299 ;
        RECT  215.982 33.741 216 33.759 ;
        RECT  215.982 33.201 216 33.219 ;
        RECT  215.982 32.661 216 32.679 ;
        RECT  215.982 32.121 216 32.139 ;
        RECT  215.982 31.581 216 31.599 ;
        RECT  215.982 31.041 216 31.059 ;
        RECT  215.982 30.501 216 30.519 ;
        RECT  215.982 29.961 216 29.979 ;
        RECT  215.982 29.421 216 29.439 ;
        RECT  215.982 28.881 216 28.899 ;
        RECT  215.982 28.341 216 28.359 ;
        RECT  215.982 27.801 216 27.819 ;
        RECT  215.982 27.261 216 27.279 ;
        RECT  215.982 26.721 216 26.739 ;
        RECT  215.982 26.181 216 26.199 ;
        RECT  215.982 25.641 216 25.659 ;
        RECT  215.982 25.101 216 25.119 ;
        RECT  215.982 24.561 216 24.579 ;
        RECT  215.982 24.021 216 24.039 ;
        RECT  215.982 23.481 216 23.499 ;
        RECT  215.982 22.941 216 22.959 ;
        RECT  215.982 22.401 216 22.419 ;
        RECT  215.982 21.861 216 21.879 ;
        RECT  215.982 21.321 216 21.339 ;
        RECT  215.982 20.781 216 20.799 ;
        RECT  215.982 20.241 216 20.259 ;
        RECT  215.982 19.701 216 19.719 ;
        RECT  215.982 19.161 216 19.179 ;
        RECT  215.982 18.621 216 18.639 ;
        RECT  215.982 18.081 216 18.099 ;
        RECT  215.982 17.541 216 17.559 ;
        RECT  215.982 17.001 216 17.019 ;
        RECT  215.982 16.461 216 16.479 ;
        RECT  215.982 15.921 216 15.939 ;
        RECT  215.982 15.381 216 15.399 ;
        RECT  215.982 14.841 216 14.859 ;
        RECT  215.982 14.301 216 14.319 ;
        RECT  215.982 13.761 216 13.779 ;
        RECT  215.982 13.221 216 13.239 ;
        RECT  215.982 12.681 216 12.699 ;
        RECT  215.982 12.141 216 12.159 ;
        RECT  215.982 11.601 216 11.619 ;
        RECT  215.982 11.061 216 11.079 ;
        RECT  215.982 10.521 216 10.539 ;
        RECT  215.982 9.981 216 9.999 ;
        RECT  215.982 9.441 216 9.459 ;
        RECT  215.982 8.901 216 8.919 ;
        RECT  215.982 8.361 216 8.379 ;
        RECT  215.982 7.821 216 7.839 ;
        RECT  215.982 7.281 216 7.299 ;
        RECT  215.982 6.741 216 6.759 ;
        RECT  215.982 6.201 216 6.219 ;
        RECT  215.982 5.661 216 5.679 ;
        RECT  215.982 5.121 216 5.139 ;
        RECT  215.982 4.581 216 4.599 ;
        RECT  215.982 4.041 216 4.059 ;
        RECT  215.982 3.501 216 3.519 ;
        RECT  215.982 2.961 216 2.979 ;
        RECT  215.982 2.421 216 2.439 ;
        RECT  215.982 1.881 216 1.899 ;
        RECT  215.982 1.341 216 1.359 ;
        RECT  215.982 0.801 216 0.819 ;
        RECT  215.982 215.181 216 215.199 ;
        RECT  0 215.181 0.018 215.199 ;
        RECT  215.982 214.641 216 214.659 ;
        RECT  0 214.641 0.018 214.659 ;
        RECT  215.982 214.101 216 214.119 ;
        RECT  0 214.101 0.018 214.119 ;
        RECT  215.982 213.561 216 213.579 ;
        RECT  0 213.561 0.018 213.579 ;
        RECT  215.982 213.021 216 213.039 ;
        RECT  0 213.021 0.018 213.039 ;
        RECT  215.982 212.481 216 212.499 ;
        RECT  0 212.481 0.018 212.499 ;
        RECT  215.982 211.941 216 211.959 ;
        RECT  0 211.941 0.018 211.959 ;
        RECT  215.982 211.401 216 211.419 ;
        RECT  0 211.401 0.018 211.419 ;
        RECT  215.982 210.861 216 210.879 ;
        RECT  0 210.861 0.018 210.879 ;
        RECT  215.982 210.321 216 210.339 ;
        RECT  0 210.321 0.018 210.339 ;
        RECT  215.982 209.781 216 209.799 ;
        RECT  0 209.781 0.018 209.799 ;
        RECT  215.982 209.241 216 209.259 ;
        RECT  0 209.241 0.018 209.259 ;
        RECT  215.982 208.701 216 208.719 ;
        RECT  0 208.701 0.018 208.719 ;
        RECT  215.982 208.161 216 208.179 ;
        RECT  0 208.161 0.018 208.179 ;
        RECT  215.982 207.621 216 207.639 ;
        RECT  0 207.621 0.018 207.639 ;
        RECT  215.982 207.081 216 207.099 ;
        RECT  0 207.081 0.018 207.099 ;
        RECT  215.982 206.541 216 206.559 ;
        RECT  0 206.541 0.018 206.559 ;
        RECT  215.982 206.001 216 206.019 ;
        RECT  0 206.001 0.018 206.019 ;
        RECT  215.982 205.461 216 205.479 ;
        RECT  0 205.461 0.018 205.479 ;
        RECT  215.982 204.921 216 204.939 ;
        RECT  0 204.921 0.018 204.939 ;
        RECT  215.982 204.381 216 204.399 ;
        RECT  0 204.381 0.018 204.399 ;
        RECT  215.982 203.841 216 203.859 ;
        RECT  0 203.841 0.018 203.859 ;
        RECT  215.982 203.301 216 203.319 ;
        RECT  0 203.301 0.018 203.319 ;
        RECT  215.982 202.761 216 202.779 ;
        RECT  0 202.761 0.018 202.779 ;
        RECT  215.982 202.221 216 202.239 ;
        RECT  0 202.221 0.018 202.239 ;
        RECT  215.982 201.681 216 201.699 ;
        RECT  0 201.681 0.018 201.699 ;
        RECT  215.982 201.141 216 201.159 ;
        RECT  0 201.141 0.018 201.159 ;
        RECT  215.982 200.601 216 200.619 ;
        RECT  0 200.601 0.018 200.619 ;
        RECT  215.982 200.061 216 200.079 ;
        RECT  0 200.061 0.018 200.079 ;
        RECT  215.982 199.521 216 199.539 ;
        RECT  0 199.521 0.018 199.539 ;
        RECT  215.982 198.981 216 198.999 ;
        RECT  0 198.981 0.018 198.999 ;
        RECT  215.982 198.441 216 198.459 ;
        RECT  0 198.441 0.018 198.459 ;
        RECT  215.982 197.901 216 197.919 ;
        RECT  0 197.901 0.018 197.919 ;
        RECT  215.982 197.361 216 197.379 ;
        RECT  0 197.361 0.018 197.379 ;
        RECT  215.982 196.821 216 196.839 ;
        RECT  0 196.821 0.018 196.839 ;
        RECT  215.982 196.281 216 196.299 ;
        RECT  0 196.281 0.018 196.299 ;
        RECT  215.982 195.741 216 195.759 ;
        RECT  0 195.741 0.018 195.759 ;
        RECT  215.982 195.201 216 195.219 ;
        RECT  0 195.201 0.018 195.219 ;
        RECT  215.982 194.661 216 194.679 ;
        RECT  0 194.661 0.018 194.679 ;
        RECT  215.982 194.121 216 194.139 ;
        RECT  0 194.121 0.018 194.139 ;
        RECT  215.982 193.581 216 193.599 ;
        RECT  0 193.581 0.018 193.599 ;
        RECT  215.982 193.041 216 193.059 ;
        RECT  0 193.041 0.018 193.059 ;
        RECT  215.982 192.501 216 192.519 ;
        RECT  0 192.501 0.018 192.519 ;
        RECT  215.982 191.961 216 191.979 ;
        RECT  0 191.961 0.018 191.979 ;
        RECT  215.982 191.421 216 191.439 ;
        RECT  0 191.421 0.018 191.439 ;
        RECT  215.982 190.881 216 190.899 ;
        RECT  0 190.881 0.018 190.899 ;
        RECT  215.982 190.341 216 190.359 ;
        RECT  0 190.341 0.018 190.359 ;
        RECT  215.982 189.801 216 189.819 ;
        RECT  0 189.801 0.018 189.819 ;
        RECT  215.982 189.261 216 189.279 ;
        RECT  0 189.261 0.018 189.279 ;
        RECT  215.982 188.721 216 188.739 ;
        RECT  0 188.721 0.018 188.739 ;
        RECT  215.982 188.181 216 188.199 ;
        RECT  0 188.181 0.018 188.199 ;
        RECT  215.982 187.641 216 187.659 ;
        RECT  0 187.641 0.018 187.659 ;
        RECT  215.982 187.101 216 187.119 ;
        RECT  0 187.101 0.018 187.119 ;
        RECT  215.982 186.561 216 186.579 ;
        RECT  0 186.561 0.018 186.579 ;
        RECT  215.982 186.021 216 186.039 ;
        RECT  0 186.021 0.018 186.039 ;
        RECT  215.982 185.481 216 185.499 ;
        RECT  0 185.481 0.018 185.499 ;
        RECT  215.982 184.941 216 184.959 ;
        RECT  0 184.941 0.018 184.959 ;
        RECT  215.982 184.401 216 184.419 ;
        RECT  0 184.401 0.018 184.419 ;
        RECT  215.982 183.861 216 183.879 ;
        RECT  0 183.861 0.018 183.879 ;
        RECT  215.982 183.321 216 183.339 ;
        RECT  0 183.321 0.018 183.339 ;
        RECT  215.982 182.781 216 182.799 ;
        RECT  0 182.781 0.018 182.799 ;
        RECT  215.982 182.241 216 182.259 ;
        RECT  0 182.241 0.018 182.259 ;
        RECT  215.982 181.701 216 181.719 ;
        RECT  0 181.701 0.018 181.719 ;
        RECT  215.982 181.161 216 181.179 ;
        RECT  0 181.161 0.018 181.179 ;
        RECT  215.982 180.621 216 180.639 ;
        RECT  0 180.621 0.018 180.639 ;
        RECT  215.982 180.081 216 180.099 ;
        RECT  0 180.081 0.018 180.099 ;
        RECT  215.982 179.541 216 179.559 ;
        RECT  0 179.541 0.018 179.559 ;
        RECT  215.982 179.001 216 179.019 ;
        RECT  0 179.001 0.018 179.019 ;
        RECT  215.982 178.461 216 178.479 ;
        RECT  0 178.461 0.018 178.479 ;
        RECT  215.982 177.921 216 177.939 ;
        RECT  0 177.921 0.018 177.939 ;
        RECT  215.982 177.381 216 177.399 ;
        RECT  0 177.381 0.018 177.399 ;
        RECT  215.982 176.841 216 176.859 ;
        RECT  0 176.841 0.018 176.859 ;
        RECT  215.982 176.301 216 176.319 ;
        RECT  0 176.301 0.018 176.319 ;
        RECT  215.982 175.761 216 175.779 ;
        RECT  0 175.761 0.018 175.779 ;
    END
  END VDD
  PIN VSS
    DIRECTION INOUT ;
    USE GROUND ;
    PORT
      LAYER M7 ;
        RECT  206.056 0.531 206.344 215.469 ;
        RECT  195.256 0.531 195.544 215.469 ;
        RECT  184.456 0.531 184.744 215.469 ;
        RECT  173.656 0.531 173.944 215.469 ;
        RECT  162.856 0.531 163.144 215.469 ;
        RECT  152.056 0.531 152.344 215.469 ;
        RECT  141.256 0.531 141.544 215.469 ;
        RECT  130.456 0.531 130.744 215.469 ;
        RECT  119.656 0.531 119.944 215.469 ;
        RECT  108.856 0.531 109.144 215.469 ;
        RECT  98.056 0.531 98.344 215.469 ;
        RECT  87.256 0.531 87.544 215.469 ;
        RECT  76.456 0.531 76.744 215.469 ;
        RECT  65.656 0.531 65.944 215.469 ;
        RECT  54.856 0.531 55.144 215.469 ;
        RECT  44.056 0.531 44.344 215.469 ;
        RECT  33.256 0.531 33.544 215.469 ;
        RECT  22.456 0.531 22.744 215.469 ;
        RECT  11.656 0.531 11.944 215.469 ;
        RECT  0.856 0.531 1.144 215.469 ;
      LAYER M6 ;
        RECT  215.968 211.596 216 211.884 ;
        RECT  0 211.596 0.032 211.884 ;
        RECT  215.968 206.196 216 206.484 ;
        RECT  0 206.196 0.032 206.484 ;
        RECT  215.968 200.796 216 201.084 ;
        RECT  0 200.796 0.032 201.084 ;
        RECT  215.968 195.396 216 195.684 ;
        RECT  0 195.396 0.032 195.684 ;
        RECT  215.968 189.996 216 190.284 ;
        RECT  0 189.996 0.032 190.284 ;
        RECT  215.968 184.596 216 184.884 ;
        RECT  0 184.596 0.032 184.884 ;
        RECT  215.968 179.196 216 179.484 ;
        RECT  0 179.196 0.032 179.484 ;
        RECT  215.968 173.796 216 174.084 ;
        RECT  0 173.796 0.032 174.084 ;
        RECT  215.968 168.396 216 168.684 ;
        RECT  0 168.396 0.032 168.684 ;
        RECT  215.968 162.996 216 163.284 ;
        RECT  0 162.996 0.032 163.284 ;
        RECT  215.968 157.596 216 157.884 ;
        RECT  0 157.596 0.032 157.884 ;
        RECT  215.968 152.196 216 152.484 ;
        RECT  0 152.196 0.032 152.484 ;
        RECT  215.968 146.796 216 147.084 ;
        RECT  0 146.796 0.032 147.084 ;
        RECT  215.968 141.396 216 141.684 ;
        RECT  0 141.396 0.032 141.684 ;
        RECT  215.968 135.996 216 136.284 ;
        RECT  0 135.996 0.032 136.284 ;
        RECT  215.968 130.596 216 130.884 ;
        RECT  0 130.596 0.032 130.884 ;
        RECT  215.968 125.196 216 125.484 ;
        RECT  0 125.196 0.032 125.484 ;
        RECT  215.968 119.796 216 120.084 ;
        RECT  0 119.796 0.032 120.084 ;
        RECT  215.968 114.396 216 114.684 ;
        RECT  0 114.396 0.032 114.684 ;
        RECT  215.968 108.996 216 109.284 ;
        RECT  0 108.996 0.032 109.284 ;
        RECT  215.968 103.596 216 103.884 ;
        RECT  0 103.596 0.032 103.884 ;
        RECT  215.968 98.196 216 98.484 ;
        RECT  0 98.196 0.032 98.484 ;
        RECT  215.968 92.796 216 93.084 ;
        RECT  0 92.796 0.032 93.084 ;
        RECT  215.968 87.396 216 87.684 ;
        RECT  0 87.396 0.032 87.684 ;
        RECT  215.968 81.996 216 82.284 ;
        RECT  0 81.996 0.032 82.284 ;
        RECT  215.968 76.596 216 76.884 ;
        RECT  0 76.596 0.032 76.884 ;
        RECT  215.968 71.196 216 71.484 ;
        RECT  0 71.196 0.032 71.484 ;
        RECT  215.968 65.796 216 66.084 ;
        RECT  0 65.796 0.032 66.084 ;
        RECT  215.968 60.396 216 60.684 ;
        RECT  0 60.396 0.032 60.684 ;
        RECT  215.968 54.996 216 55.284 ;
        RECT  0 54.996 0.032 55.284 ;
        RECT  215.968 49.596 216 49.884 ;
        RECT  0 49.596 0.032 49.884 ;
        RECT  215.968 44.196 216 44.484 ;
        RECT  0 44.196 0.032 44.484 ;
        RECT  215.968 38.796 216 39.084 ;
        RECT  0 38.796 0.032 39.084 ;
        RECT  215.968 33.396 216 33.684 ;
        RECT  0 33.396 0.032 33.684 ;
        RECT  215.968 27.996 216 28.284 ;
        RECT  0 27.996 0.032 28.284 ;
        RECT  215.968 22.596 216 22.884 ;
        RECT  0 22.596 0.032 22.884 ;
        RECT  215.968 17.196 216 17.484 ;
        RECT  0 17.196 0.032 17.484 ;
        RECT  215.968 11.796 216 12.084 ;
        RECT  0 11.796 0.032 12.084 ;
        RECT  215.968 6.396 216 6.684 ;
        RECT  0 6.396 0.032 6.684 ;
        RECT  215.968 0.996 216 1.284 ;
        RECT  0 0.996 0.032 1.284 ;
      LAYER M2 ;
        RECT  215.982 174.951 216 174.969 ;
        RECT  215.982 174.411 216 174.429 ;
        RECT  215.982 173.871 216 173.889 ;
        RECT  215.982 173.331 216 173.349 ;
        RECT  215.982 172.791 216 172.809 ;
        RECT  215.982 172.251 216 172.269 ;
        RECT  215.982 171.711 216 171.729 ;
        RECT  215.982 171.171 216 171.189 ;
        RECT  215.982 170.631 216 170.649 ;
        RECT  215.982 170.091 216 170.109 ;
        RECT  215.982 169.551 216 169.569 ;
        RECT  215.982 169.011 216 169.029 ;
        RECT  215.982 168.471 216 168.489 ;
        RECT  215.982 167.931 216 167.949 ;
        RECT  215.982 167.391 216 167.409 ;
        RECT  215.982 166.851 216 166.869 ;
        RECT  215.982 166.311 216 166.329 ;
        RECT  215.982 165.771 216 165.789 ;
        RECT  215.982 165.231 216 165.249 ;
        RECT  215.982 164.691 216 164.709 ;
        RECT  215.982 164.151 216 164.169 ;
        RECT  215.982 163.611 216 163.629 ;
        RECT  215.982 163.071 216 163.089 ;
        RECT  215.982 162.531 216 162.549 ;
        RECT  215.982 161.991 216 162.009 ;
        RECT  215.982 161.451 216 161.469 ;
        RECT  215.982 160.911 216 160.929 ;
        RECT  215.982 160.371 216 160.389 ;
        RECT  215.982 159.831 216 159.849 ;
        RECT  215.982 159.291 216 159.309 ;
        RECT  215.982 158.751 216 158.769 ;
        RECT  215.982 158.211 216 158.229 ;
        RECT  215.982 157.671 216 157.689 ;
        RECT  215.982 157.131 216 157.149 ;
        RECT  215.982 156.591 216 156.609 ;
        RECT  215.982 156.051 216 156.069 ;
        RECT  215.982 155.511 216 155.529 ;
        RECT  215.982 154.971 216 154.989 ;
        RECT  215.982 154.431 216 154.449 ;
        RECT  215.982 153.891 216 153.909 ;
        RECT  215.982 153.351 216 153.369 ;
        RECT  215.982 152.811 216 152.829 ;
        RECT  215.982 152.271 216 152.289 ;
        RECT  215.982 151.731 216 151.749 ;
        RECT  215.982 151.191 216 151.209 ;
        RECT  215.982 150.651 216 150.669 ;
        RECT  215.982 150.111 216 150.129 ;
        RECT  215.982 149.571 216 149.589 ;
        RECT  215.982 149.031 216 149.049 ;
        RECT  215.982 148.491 216 148.509 ;
        RECT  215.982 147.951 216 147.969 ;
        RECT  215.982 147.411 216 147.429 ;
        RECT  215.982 146.871 216 146.889 ;
        RECT  215.982 146.331 216 146.349 ;
        RECT  215.982 145.791 216 145.809 ;
        RECT  215.982 145.251 216 145.269 ;
        RECT  215.982 144.711 216 144.729 ;
        RECT  215.982 144.171 216 144.189 ;
        RECT  215.982 143.631 216 143.649 ;
        RECT  215.982 143.091 216 143.109 ;
        RECT  215.982 142.551 216 142.569 ;
        RECT  215.982 142.011 216 142.029 ;
        RECT  215.982 141.471 216 141.489 ;
        RECT  215.982 140.931 216 140.949 ;
        RECT  215.982 140.391 216 140.409 ;
        RECT  215.982 139.851 216 139.869 ;
        RECT  215.982 139.311 216 139.329 ;
        RECT  215.982 138.771 216 138.789 ;
        RECT  215.982 138.231 216 138.249 ;
        RECT  215.982 137.691 216 137.709 ;
        RECT  215.982 137.151 216 137.169 ;
        RECT  215.982 136.611 216 136.629 ;
        RECT  215.982 136.071 216 136.089 ;
        RECT  215.982 135.531 216 135.549 ;
        RECT  215.982 134.991 216 135.009 ;
        RECT  215.982 134.451 216 134.469 ;
        RECT  215.982 133.911 216 133.929 ;
        RECT  215.982 133.371 216 133.389 ;
        RECT  215.982 132.831 216 132.849 ;
        RECT  215.982 132.291 216 132.309 ;
        RECT  215.982 131.751 216 131.769 ;
        RECT  215.982 131.211 216 131.229 ;
        RECT  215.982 130.671 216 130.689 ;
        RECT  215.982 130.131 216 130.149 ;
        RECT  215.982 129.591 216 129.609 ;
        RECT  215.982 129.051 216 129.069 ;
        RECT  215.982 128.511 216 128.529 ;
        RECT  215.982 127.971 216 127.989 ;
        RECT  215.982 127.431 216 127.449 ;
        RECT  215.982 126.891 216 126.909 ;
        RECT  215.982 126.351 216 126.369 ;
        RECT  215.982 125.811 216 125.829 ;
        RECT  215.982 125.271 216 125.289 ;
        RECT  215.982 124.731 216 124.749 ;
        RECT  215.982 124.191 216 124.209 ;
        RECT  215.982 123.651 216 123.669 ;
        RECT  215.982 123.111 216 123.129 ;
        RECT  215.982 122.571 216 122.589 ;
        RECT  215.982 122.031 216 122.049 ;
        RECT  215.982 121.491 216 121.509 ;
        RECT  215.982 120.951 216 120.969 ;
        RECT  215.982 120.411 216 120.429 ;
        RECT  215.982 119.871 216 119.889 ;
        RECT  215.982 119.331 216 119.349 ;
        RECT  215.982 118.791 216 118.809 ;
        RECT  215.982 118.251 216 118.269 ;
        RECT  215.982 117.711 216 117.729 ;
        RECT  215.982 117.171 216 117.189 ;
        RECT  215.982 116.631 216 116.649 ;
        RECT  215.982 116.091 216 116.109 ;
        RECT  215.982 115.551 216 115.569 ;
        RECT  215.982 115.011 216 115.029 ;
        RECT  215.982 114.471 216 114.489 ;
        RECT  215.982 113.931 216 113.949 ;
        RECT  215.982 113.391 216 113.409 ;
        RECT  215.982 112.851 216 112.869 ;
        RECT  215.982 112.311 216 112.329 ;
        RECT  215.982 111.771 216 111.789 ;
        RECT  215.982 111.231 216 111.249 ;
        RECT  215.982 110.691 216 110.709 ;
        RECT  215.982 110.151 216 110.169 ;
        RECT  215.982 109.611 216 109.629 ;
        RECT  215.982 109.071 216 109.089 ;
        RECT  215.982 108.531 216 108.549 ;
        RECT  215.982 107.991 216 108.009 ;
        RECT  215.982 107.451 216 107.469 ;
        RECT  215.982 106.911 216 106.929 ;
        RECT  215.982 106.371 216 106.389 ;
        RECT  215.982 105.831 216 105.849 ;
        RECT  215.982 105.291 216 105.309 ;
        RECT  215.982 104.751 216 104.769 ;
        RECT  215.982 104.211 216 104.229 ;
        RECT  215.982 103.671 216 103.689 ;
        RECT  215.982 103.131 216 103.149 ;
        RECT  215.982 102.591 216 102.609 ;
        RECT  215.982 102.051 216 102.069 ;
        RECT  215.982 101.511 216 101.529 ;
        RECT  215.982 100.971 216 100.989 ;
        RECT  215.982 100.431 216 100.449 ;
        RECT  215.982 99.891 216 99.909 ;
        RECT  215.982 99.351 216 99.369 ;
        RECT  215.982 98.811 216 98.829 ;
        RECT  215.982 98.271 216 98.289 ;
        RECT  215.982 97.731 216 97.749 ;
        RECT  215.982 97.191 216 97.209 ;
        RECT  215.982 96.651 216 96.669 ;
        RECT  215.982 96.111 216 96.129 ;
        RECT  215.982 95.571 216 95.589 ;
        RECT  215.982 95.031 216 95.049 ;
        RECT  215.982 94.491 216 94.509 ;
        RECT  215.982 93.951 216 93.969 ;
        RECT  215.982 93.411 216 93.429 ;
        RECT  215.982 92.871 216 92.889 ;
        RECT  215.982 92.331 216 92.349 ;
        RECT  215.982 91.791 216 91.809 ;
        RECT  215.982 91.251 216 91.269 ;
        RECT  215.982 90.711 216 90.729 ;
        RECT  215.982 90.171 216 90.189 ;
        RECT  215.982 89.631 216 89.649 ;
        RECT  215.982 89.091 216 89.109 ;
        RECT  215.982 88.551 216 88.569 ;
        RECT  215.982 88.011 216 88.029 ;
        RECT  215.982 87.471 216 87.489 ;
        RECT  215.982 86.931 216 86.949 ;
        RECT  215.982 86.391 216 86.409 ;
        RECT  215.982 85.851 216 85.869 ;
        RECT  215.982 85.311 216 85.329 ;
        RECT  215.982 84.771 216 84.789 ;
        RECT  215.982 84.231 216 84.249 ;
        RECT  215.982 83.691 216 83.709 ;
        RECT  215.982 83.151 216 83.169 ;
        RECT  215.982 82.611 216 82.629 ;
        RECT  215.982 82.071 216 82.089 ;
        RECT  215.982 81.531 216 81.549 ;
        RECT  215.982 80.991 216 81.009 ;
        RECT  215.982 80.451 216 80.469 ;
        RECT  215.982 79.911 216 79.929 ;
        RECT  215.982 79.371 216 79.389 ;
        RECT  215.982 78.831 216 78.849 ;
        RECT  215.982 78.291 216 78.309 ;
        RECT  215.982 77.751 216 77.769 ;
        RECT  215.982 77.211 216 77.229 ;
        RECT  215.982 76.671 216 76.689 ;
        RECT  215.982 76.131 216 76.149 ;
        RECT  215.982 75.591 216 75.609 ;
        RECT  215.982 75.051 216 75.069 ;
        RECT  215.982 74.511 216 74.529 ;
        RECT  215.982 73.971 216 73.989 ;
        RECT  215.982 73.431 216 73.449 ;
        RECT  215.982 72.891 216 72.909 ;
        RECT  215.982 72.351 216 72.369 ;
        RECT  215.982 71.811 216 71.829 ;
        RECT  215.982 71.271 216 71.289 ;
        RECT  215.982 70.731 216 70.749 ;
        RECT  215.982 70.191 216 70.209 ;
        RECT  215.982 69.651 216 69.669 ;
        RECT  215.982 69.111 216 69.129 ;
        RECT  215.982 68.571 216 68.589 ;
        RECT  215.982 68.031 216 68.049 ;
        RECT  215.982 67.491 216 67.509 ;
        RECT  215.982 66.951 216 66.969 ;
        RECT  215.982 66.411 216 66.429 ;
        RECT  215.982 65.871 216 65.889 ;
        RECT  215.982 65.331 216 65.349 ;
        RECT  215.982 64.791 216 64.809 ;
        RECT  215.982 64.251 216 64.269 ;
        RECT  215.982 63.711 216 63.729 ;
        RECT  215.982 63.171 216 63.189 ;
        RECT  215.982 62.631 216 62.649 ;
        RECT  215.982 62.091 216 62.109 ;
        RECT  215.982 61.551 216 61.569 ;
        RECT  215.982 61.011 216 61.029 ;
        RECT  215.982 60.471 216 60.489 ;
        RECT  215.982 59.931 216 59.949 ;
        RECT  215.982 59.391 216 59.409 ;
        RECT  215.982 58.851 216 58.869 ;
        RECT  215.982 58.311 216 58.329 ;
        RECT  215.982 57.771 216 57.789 ;
        RECT  215.982 57.231 216 57.249 ;
        RECT  215.982 56.691 216 56.709 ;
        RECT  215.982 56.151 216 56.169 ;
        RECT  215.982 55.611 216 55.629 ;
        RECT  215.982 55.071 216 55.089 ;
        RECT  215.982 54.531 216 54.549 ;
        RECT  215.982 53.991 216 54.009 ;
        RECT  215.982 53.451 216 53.469 ;
        RECT  215.982 52.911 216 52.929 ;
        RECT  215.982 52.371 216 52.389 ;
        RECT  215.982 51.831 216 51.849 ;
        RECT  215.982 51.291 216 51.309 ;
        RECT  215.982 50.751 216 50.769 ;
        RECT  215.982 50.211 216 50.229 ;
        RECT  215.982 49.671 216 49.689 ;
        RECT  215.982 49.131 216 49.149 ;
        RECT  215.982 48.591 216 48.609 ;
        RECT  215.982 48.051 216 48.069 ;
        RECT  215.982 47.511 216 47.529 ;
        RECT  215.982 46.971 216 46.989 ;
        RECT  215.982 46.431 216 46.449 ;
        RECT  215.982 45.891 216 45.909 ;
        RECT  215.982 45.351 216 45.369 ;
        RECT  215.982 44.811 216 44.829 ;
        RECT  215.982 44.271 216 44.289 ;
        RECT  215.982 43.731 216 43.749 ;
        RECT  215.982 43.191 216 43.209 ;
        RECT  215.982 42.651 216 42.669 ;
        RECT  215.982 42.111 216 42.129 ;
        RECT  215.982 41.571 216 41.589 ;
        RECT  215.982 41.031 216 41.049 ;
        RECT  215.982 40.491 216 40.509 ;
        RECT  215.982 39.951 216 39.969 ;
        RECT  215.982 39.411 216 39.429 ;
        RECT  215.982 38.871 216 38.889 ;
        RECT  215.982 38.331 216 38.349 ;
        RECT  215.982 37.791 216 37.809 ;
        RECT  215.982 37.251 216 37.269 ;
        RECT  215.982 36.711 216 36.729 ;
        RECT  215.982 36.171 216 36.189 ;
        RECT  215.982 35.631 216 35.649 ;
        RECT  215.982 35.091 216 35.109 ;
        RECT  215.982 34.551 216 34.569 ;
        RECT  215.982 34.011 216 34.029 ;
        RECT  215.982 33.471 216 33.489 ;
        RECT  215.982 32.931 216 32.949 ;
        RECT  215.982 32.391 216 32.409 ;
        RECT  215.982 31.851 216 31.869 ;
        RECT  215.982 31.311 216 31.329 ;
        RECT  215.982 30.771 216 30.789 ;
        RECT  215.982 30.231 216 30.249 ;
        RECT  215.982 29.691 216 29.709 ;
        RECT  215.982 29.151 216 29.169 ;
        RECT  215.982 28.611 216 28.629 ;
        RECT  215.982 28.071 216 28.089 ;
        RECT  215.982 27.531 216 27.549 ;
        RECT  215.982 26.991 216 27.009 ;
        RECT  215.982 26.451 216 26.469 ;
        RECT  215.982 25.911 216 25.929 ;
        RECT  215.982 25.371 216 25.389 ;
        RECT  215.982 24.831 216 24.849 ;
        RECT  215.982 24.291 216 24.309 ;
        RECT  215.982 23.751 216 23.769 ;
        RECT  215.982 23.211 216 23.229 ;
        RECT  215.982 22.671 216 22.689 ;
        RECT  215.982 22.131 216 22.149 ;
        RECT  215.982 21.591 216 21.609 ;
        RECT  215.982 21.051 216 21.069 ;
        RECT  215.982 20.511 216 20.529 ;
        RECT  215.982 19.971 216 19.989 ;
        RECT  215.982 19.431 216 19.449 ;
        RECT  215.982 18.891 216 18.909 ;
        RECT  215.982 18.351 216 18.369 ;
        RECT  215.982 17.811 216 17.829 ;
        RECT  215.982 17.271 216 17.289 ;
        RECT  215.982 16.731 216 16.749 ;
        RECT  215.982 16.191 216 16.209 ;
        RECT  215.982 15.651 216 15.669 ;
        RECT  215.982 15.111 216 15.129 ;
        RECT  215.982 14.571 216 14.589 ;
        RECT  215.982 14.031 216 14.049 ;
        RECT  215.982 13.491 216 13.509 ;
        RECT  215.982 12.951 216 12.969 ;
        RECT  215.982 12.411 216 12.429 ;
        RECT  215.982 11.871 216 11.889 ;
        RECT  215.982 11.331 216 11.349 ;
        RECT  215.982 10.791 216 10.809 ;
        RECT  215.982 10.251 216 10.269 ;
        RECT  215.982 9.711 216 9.729 ;
        RECT  215.982 9.171 216 9.189 ;
        RECT  215.982 8.631 216 8.649 ;
        RECT  215.982 8.091 216 8.109 ;
        RECT  215.982 7.551 216 7.569 ;
        RECT  215.982 7.011 216 7.029 ;
        RECT  215.982 6.471 216 6.489 ;
        RECT  215.982 5.931 216 5.949 ;
        RECT  215.982 5.391 216 5.409 ;
        RECT  215.982 4.851 216 4.869 ;
        RECT  215.982 4.311 216 4.329 ;
        RECT  215.982 3.771 216 3.789 ;
        RECT  215.982 3.231 216 3.249 ;
        RECT  215.982 2.691 216 2.709 ;
        RECT  215.982 2.151 216 2.169 ;
        RECT  215.982 1.611 216 1.629 ;
        RECT  215.982 1.071 216 1.089 ;
        RECT  215.982 0.531 216 0.549 ;
        RECT  215.982 215.451 216 215.469 ;
        RECT  0 215.451 0.018 215.469 ;
        RECT  215.982 214.911 216 214.929 ;
        RECT  0 214.911 0.018 214.929 ;
        RECT  215.982 214.371 216 214.389 ;
        RECT  0 214.371 0.018 214.389 ;
        RECT  215.982 213.831 216 213.849 ;
        RECT  0 213.831 0.018 213.849 ;
        RECT  215.982 213.291 216 213.309 ;
        RECT  0 213.291 0.018 213.309 ;
        RECT  215.982 212.751 216 212.769 ;
        RECT  0 212.751 0.018 212.769 ;
        RECT  215.982 212.211 216 212.229 ;
        RECT  0 212.211 0.018 212.229 ;
        RECT  215.982 211.671 216 211.689 ;
        RECT  0 211.671 0.018 211.689 ;
        RECT  215.982 211.131 216 211.149 ;
        RECT  0 211.131 0.018 211.149 ;
        RECT  215.982 210.591 216 210.609 ;
        RECT  0 210.591 0.018 210.609 ;
        RECT  215.982 210.051 216 210.069 ;
        RECT  0 210.051 0.018 210.069 ;
        RECT  215.982 209.511 216 209.529 ;
        RECT  0 209.511 0.018 209.529 ;
        RECT  215.982 208.971 216 208.989 ;
        RECT  0 208.971 0.018 208.989 ;
        RECT  215.982 208.431 216 208.449 ;
        RECT  0 208.431 0.018 208.449 ;
        RECT  215.982 207.891 216 207.909 ;
        RECT  0 207.891 0.018 207.909 ;
        RECT  215.982 207.351 216 207.369 ;
        RECT  0 207.351 0.018 207.369 ;
        RECT  215.982 206.811 216 206.829 ;
        RECT  0 206.811 0.018 206.829 ;
        RECT  215.982 206.271 216 206.289 ;
        RECT  0 206.271 0.018 206.289 ;
        RECT  215.982 205.731 216 205.749 ;
        RECT  0 205.731 0.018 205.749 ;
        RECT  215.982 205.191 216 205.209 ;
        RECT  0 205.191 0.018 205.209 ;
        RECT  215.982 204.651 216 204.669 ;
        RECT  0 204.651 0.018 204.669 ;
        RECT  215.982 204.111 216 204.129 ;
        RECT  0 204.111 0.018 204.129 ;
        RECT  215.982 203.571 216 203.589 ;
        RECT  0 203.571 0.018 203.589 ;
        RECT  215.982 203.031 216 203.049 ;
        RECT  0 203.031 0.018 203.049 ;
        RECT  215.982 202.491 216 202.509 ;
        RECT  0 202.491 0.018 202.509 ;
        RECT  215.982 201.951 216 201.969 ;
        RECT  0 201.951 0.018 201.969 ;
        RECT  215.982 201.411 216 201.429 ;
        RECT  0 201.411 0.018 201.429 ;
        RECT  215.982 200.871 216 200.889 ;
        RECT  0 200.871 0.018 200.889 ;
        RECT  215.982 200.331 216 200.349 ;
        RECT  0 200.331 0.018 200.349 ;
        RECT  215.982 199.791 216 199.809 ;
        RECT  0 199.791 0.018 199.809 ;
        RECT  215.982 199.251 216 199.269 ;
        RECT  0 199.251 0.018 199.269 ;
        RECT  215.982 198.711 216 198.729 ;
        RECT  0 198.711 0.018 198.729 ;
        RECT  215.982 198.171 216 198.189 ;
        RECT  0 198.171 0.018 198.189 ;
        RECT  215.982 197.631 216 197.649 ;
        RECT  0 197.631 0.018 197.649 ;
        RECT  215.982 197.091 216 197.109 ;
        RECT  0 197.091 0.018 197.109 ;
        RECT  215.982 196.551 216 196.569 ;
        RECT  0 196.551 0.018 196.569 ;
        RECT  215.982 196.011 216 196.029 ;
        RECT  0 196.011 0.018 196.029 ;
        RECT  215.982 195.471 216 195.489 ;
        RECT  0 195.471 0.018 195.489 ;
        RECT  215.982 194.931 216 194.949 ;
        RECT  0 194.931 0.018 194.949 ;
        RECT  215.982 194.391 216 194.409 ;
        RECT  0 194.391 0.018 194.409 ;
        RECT  215.982 193.851 216 193.869 ;
        RECT  0 193.851 0.018 193.869 ;
        RECT  215.982 193.311 216 193.329 ;
        RECT  0 193.311 0.018 193.329 ;
        RECT  215.982 192.771 216 192.789 ;
        RECT  0 192.771 0.018 192.789 ;
        RECT  215.982 192.231 216 192.249 ;
        RECT  0 192.231 0.018 192.249 ;
        RECT  215.982 191.691 216 191.709 ;
        RECT  0 191.691 0.018 191.709 ;
        RECT  215.982 191.151 216 191.169 ;
        RECT  0 191.151 0.018 191.169 ;
        RECT  215.982 190.611 216 190.629 ;
        RECT  0 190.611 0.018 190.629 ;
        RECT  215.982 190.071 216 190.089 ;
        RECT  0 190.071 0.018 190.089 ;
        RECT  215.982 189.531 216 189.549 ;
        RECT  0 189.531 0.018 189.549 ;
        RECT  215.982 188.991 216 189.009 ;
        RECT  0 188.991 0.018 189.009 ;
        RECT  215.982 188.451 216 188.469 ;
        RECT  0 188.451 0.018 188.469 ;
        RECT  215.982 187.911 216 187.929 ;
        RECT  0 187.911 0.018 187.929 ;
        RECT  215.982 187.371 216 187.389 ;
        RECT  0 187.371 0.018 187.389 ;
        RECT  215.982 186.831 216 186.849 ;
        RECT  0 186.831 0.018 186.849 ;
        RECT  215.982 186.291 216 186.309 ;
        RECT  0 186.291 0.018 186.309 ;
        RECT  215.982 185.751 216 185.769 ;
        RECT  0 185.751 0.018 185.769 ;
        RECT  215.982 185.211 216 185.229 ;
        RECT  0 185.211 0.018 185.229 ;
        RECT  215.982 184.671 216 184.689 ;
        RECT  0 184.671 0.018 184.689 ;
        RECT  215.982 184.131 216 184.149 ;
        RECT  0 184.131 0.018 184.149 ;
        RECT  215.982 183.591 216 183.609 ;
        RECT  0 183.591 0.018 183.609 ;
        RECT  215.982 183.051 216 183.069 ;
        RECT  0 183.051 0.018 183.069 ;
        RECT  215.982 182.511 216 182.529 ;
        RECT  0 182.511 0.018 182.529 ;
        RECT  215.982 181.971 216 181.989 ;
        RECT  0 181.971 0.018 181.989 ;
        RECT  215.982 181.431 216 181.449 ;
        RECT  0 181.431 0.018 181.449 ;
        RECT  215.982 180.891 216 180.909 ;
        RECT  0 180.891 0.018 180.909 ;
        RECT  215.982 180.351 216 180.369 ;
        RECT  0 180.351 0.018 180.369 ;
        RECT  215.982 179.811 216 179.829 ;
        RECT  0 179.811 0.018 179.829 ;
        RECT  215.982 179.271 216 179.289 ;
        RECT  0 179.271 0.018 179.289 ;
        RECT  215.982 178.731 216 178.749 ;
        RECT  0 178.731 0.018 178.749 ;
        RECT  215.982 178.191 216 178.209 ;
        RECT  0 178.191 0.018 178.209 ;
        RECT  215.982 177.651 216 177.669 ;
        RECT  0 177.651 0.018 177.669 ;
        RECT  215.982 177.111 216 177.129 ;
        RECT  0 177.111 0.018 177.129 ;
        RECT  215.982 176.571 216 176.589 ;
        RECT  0 176.571 0.018 176.589 ;
        RECT  215.982 176.031 216 176.049 ;
        RECT  0 176.031 0.018 176.049 ;
        RECT  215.982 175.491 216 175.509 ;
        RECT  0 175.491 0.018 175.509 ;
      LAYER M1 ;
        RECT  215.982 174.951 216 174.969 ;
        RECT  215.982 174.411 216 174.429 ;
        RECT  215.982 173.871 216 173.889 ;
        RECT  215.982 173.331 216 173.349 ;
        RECT  215.982 172.791 216 172.809 ;
        RECT  215.982 172.251 216 172.269 ;
        RECT  215.982 171.711 216 171.729 ;
        RECT  215.982 171.171 216 171.189 ;
        RECT  215.982 170.631 216 170.649 ;
        RECT  215.982 170.091 216 170.109 ;
        RECT  215.982 169.551 216 169.569 ;
        RECT  215.982 169.011 216 169.029 ;
        RECT  215.982 168.471 216 168.489 ;
        RECT  215.982 167.931 216 167.949 ;
        RECT  215.982 167.391 216 167.409 ;
        RECT  215.982 166.851 216 166.869 ;
        RECT  215.982 166.311 216 166.329 ;
        RECT  215.982 165.771 216 165.789 ;
        RECT  215.982 165.231 216 165.249 ;
        RECT  215.982 164.691 216 164.709 ;
        RECT  215.982 164.151 216 164.169 ;
        RECT  215.982 163.611 216 163.629 ;
        RECT  215.982 163.071 216 163.089 ;
        RECT  215.982 162.531 216 162.549 ;
        RECT  215.982 161.991 216 162.009 ;
        RECT  215.982 161.451 216 161.469 ;
        RECT  215.982 160.911 216 160.929 ;
        RECT  215.982 160.371 216 160.389 ;
        RECT  215.982 159.831 216 159.849 ;
        RECT  215.982 159.291 216 159.309 ;
        RECT  215.982 158.751 216 158.769 ;
        RECT  215.982 158.211 216 158.229 ;
        RECT  215.982 157.671 216 157.689 ;
        RECT  215.982 157.131 216 157.149 ;
        RECT  215.982 156.591 216 156.609 ;
        RECT  215.982 156.051 216 156.069 ;
        RECT  215.982 155.511 216 155.529 ;
        RECT  215.982 154.971 216 154.989 ;
        RECT  215.982 154.431 216 154.449 ;
        RECT  215.982 153.891 216 153.909 ;
        RECT  215.982 153.351 216 153.369 ;
        RECT  215.982 152.811 216 152.829 ;
        RECT  215.982 152.271 216 152.289 ;
        RECT  215.982 151.731 216 151.749 ;
        RECT  215.982 151.191 216 151.209 ;
        RECT  215.982 150.651 216 150.669 ;
        RECT  215.982 150.111 216 150.129 ;
        RECT  215.982 149.571 216 149.589 ;
        RECT  215.982 149.031 216 149.049 ;
        RECT  215.982 148.491 216 148.509 ;
        RECT  215.982 147.951 216 147.969 ;
        RECT  215.982 147.411 216 147.429 ;
        RECT  215.982 146.871 216 146.889 ;
        RECT  215.982 146.331 216 146.349 ;
        RECT  215.982 145.791 216 145.809 ;
        RECT  215.982 145.251 216 145.269 ;
        RECT  215.982 144.711 216 144.729 ;
        RECT  215.982 144.171 216 144.189 ;
        RECT  215.982 143.631 216 143.649 ;
        RECT  215.982 143.091 216 143.109 ;
        RECT  215.982 142.551 216 142.569 ;
        RECT  215.982 142.011 216 142.029 ;
        RECT  215.982 141.471 216 141.489 ;
        RECT  215.982 140.931 216 140.949 ;
        RECT  215.982 140.391 216 140.409 ;
        RECT  215.982 139.851 216 139.869 ;
        RECT  215.982 139.311 216 139.329 ;
        RECT  215.982 138.771 216 138.789 ;
        RECT  215.982 138.231 216 138.249 ;
        RECT  215.982 137.691 216 137.709 ;
        RECT  215.982 137.151 216 137.169 ;
        RECT  215.982 136.611 216 136.629 ;
        RECT  215.982 136.071 216 136.089 ;
        RECT  215.982 135.531 216 135.549 ;
        RECT  215.982 134.991 216 135.009 ;
        RECT  215.982 134.451 216 134.469 ;
        RECT  215.982 133.911 216 133.929 ;
        RECT  215.982 133.371 216 133.389 ;
        RECT  215.982 132.831 216 132.849 ;
        RECT  215.982 132.291 216 132.309 ;
        RECT  215.982 131.751 216 131.769 ;
        RECT  215.982 131.211 216 131.229 ;
        RECT  215.982 130.671 216 130.689 ;
        RECT  215.982 130.131 216 130.149 ;
        RECT  215.982 129.591 216 129.609 ;
        RECT  215.982 129.051 216 129.069 ;
        RECT  215.982 128.511 216 128.529 ;
        RECT  215.982 127.971 216 127.989 ;
        RECT  215.982 127.431 216 127.449 ;
        RECT  215.982 126.891 216 126.909 ;
        RECT  215.982 126.351 216 126.369 ;
        RECT  215.982 125.811 216 125.829 ;
        RECT  215.982 125.271 216 125.289 ;
        RECT  215.982 124.731 216 124.749 ;
        RECT  215.982 124.191 216 124.209 ;
        RECT  215.982 123.651 216 123.669 ;
        RECT  215.982 123.111 216 123.129 ;
        RECT  215.982 122.571 216 122.589 ;
        RECT  215.982 122.031 216 122.049 ;
        RECT  215.982 121.491 216 121.509 ;
        RECT  215.982 120.951 216 120.969 ;
        RECT  215.982 120.411 216 120.429 ;
        RECT  215.982 119.871 216 119.889 ;
        RECT  215.982 119.331 216 119.349 ;
        RECT  215.982 118.791 216 118.809 ;
        RECT  215.982 118.251 216 118.269 ;
        RECT  215.982 117.711 216 117.729 ;
        RECT  215.982 117.171 216 117.189 ;
        RECT  215.982 116.631 216 116.649 ;
        RECT  215.982 116.091 216 116.109 ;
        RECT  215.982 115.551 216 115.569 ;
        RECT  215.982 115.011 216 115.029 ;
        RECT  215.982 114.471 216 114.489 ;
        RECT  215.982 113.931 216 113.949 ;
        RECT  215.982 113.391 216 113.409 ;
        RECT  215.982 112.851 216 112.869 ;
        RECT  215.982 112.311 216 112.329 ;
        RECT  215.982 111.771 216 111.789 ;
        RECT  215.982 111.231 216 111.249 ;
        RECT  215.982 110.691 216 110.709 ;
        RECT  215.982 110.151 216 110.169 ;
        RECT  215.982 109.611 216 109.629 ;
        RECT  215.982 109.071 216 109.089 ;
        RECT  215.982 108.531 216 108.549 ;
        RECT  215.982 107.991 216 108.009 ;
        RECT  215.982 107.451 216 107.469 ;
        RECT  215.982 106.911 216 106.929 ;
        RECT  215.982 106.371 216 106.389 ;
        RECT  215.982 105.831 216 105.849 ;
        RECT  215.982 105.291 216 105.309 ;
        RECT  215.982 104.751 216 104.769 ;
        RECT  215.982 104.211 216 104.229 ;
        RECT  215.982 103.671 216 103.689 ;
        RECT  215.982 103.131 216 103.149 ;
        RECT  215.982 102.591 216 102.609 ;
        RECT  215.982 102.051 216 102.069 ;
        RECT  215.982 101.511 216 101.529 ;
        RECT  215.982 100.971 216 100.989 ;
        RECT  215.982 100.431 216 100.449 ;
        RECT  215.982 99.891 216 99.909 ;
        RECT  215.982 99.351 216 99.369 ;
        RECT  215.982 98.811 216 98.829 ;
        RECT  215.982 98.271 216 98.289 ;
        RECT  215.982 97.731 216 97.749 ;
        RECT  215.982 97.191 216 97.209 ;
        RECT  215.982 96.651 216 96.669 ;
        RECT  215.982 96.111 216 96.129 ;
        RECT  215.982 95.571 216 95.589 ;
        RECT  215.982 95.031 216 95.049 ;
        RECT  215.982 94.491 216 94.509 ;
        RECT  215.982 93.951 216 93.969 ;
        RECT  215.982 93.411 216 93.429 ;
        RECT  215.982 92.871 216 92.889 ;
        RECT  215.982 92.331 216 92.349 ;
        RECT  215.982 91.791 216 91.809 ;
        RECT  215.982 91.251 216 91.269 ;
        RECT  215.982 90.711 216 90.729 ;
        RECT  215.982 90.171 216 90.189 ;
        RECT  215.982 89.631 216 89.649 ;
        RECT  215.982 89.091 216 89.109 ;
        RECT  215.982 88.551 216 88.569 ;
        RECT  215.982 88.011 216 88.029 ;
        RECT  215.982 87.471 216 87.489 ;
        RECT  215.982 86.931 216 86.949 ;
        RECT  215.982 86.391 216 86.409 ;
        RECT  215.982 85.851 216 85.869 ;
        RECT  215.982 85.311 216 85.329 ;
        RECT  215.982 84.771 216 84.789 ;
        RECT  215.982 84.231 216 84.249 ;
        RECT  215.982 83.691 216 83.709 ;
        RECT  215.982 83.151 216 83.169 ;
        RECT  215.982 82.611 216 82.629 ;
        RECT  215.982 82.071 216 82.089 ;
        RECT  215.982 81.531 216 81.549 ;
        RECT  215.982 80.991 216 81.009 ;
        RECT  215.982 80.451 216 80.469 ;
        RECT  215.982 79.911 216 79.929 ;
        RECT  215.982 79.371 216 79.389 ;
        RECT  215.982 78.831 216 78.849 ;
        RECT  215.982 78.291 216 78.309 ;
        RECT  215.982 77.751 216 77.769 ;
        RECT  215.982 77.211 216 77.229 ;
        RECT  215.982 76.671 216 76.689 ;
        RECT  215.982 76.131 216 76.149 ;
        RECT  215.982 75.591 216 75.609 ;
        RECT  215.982 75.051 216 75.069 ;
        RECT  215.982 74.511 216 74.529 ;
        RECT  215.982 73.971 216 73.989 ;
        RECT  215.982 73.431 216 73.449 ;
        RECT  215.982 72.891 216 72.909 ;
        RECT  215.982 72.351 216 72.369 ;
        RECT  215.982 71.811 216 71.829 ;
        RECT  215.982 71.271 216 71.289 ;
        RECT  215.982 70.731 216 70.749 ;
        RECT  215.982 70.191 216 70.209 ;
        RECT  215.982 69.651 216 69.669 ;
        RECT  215.982 69.111 216 69.129 ;
        RECT  215.982 68.571 216 68.589 ;
        RECT  215.982 68.031 216 68.049 ;
        RECT  215.982 67.491 216 67.509 ;
        RECT  215.982 66.951 216 66.969 ;
        RECT  215.982 66.411 216 66.429 ;
        RECT  215.982 65.871 216 65.889 ;
        RECT  215.982 65.331 216 65.349 ;
        RECT  215.982 64.791 216 64.809 ;
        RECT  215.982 64.251 216 64.269 ;
        RECT  215.982 63.711 216 63.729 ;
        RECT  215.982 63.171 216 63.189 ;
        RECT  215.982 62.631 216 62.649 ;
        RECT  215.982 62.091 216 62.109 ;
        RECT  215.982 61.551 216 61.569 ;
        RECT  215.982 61.011 216 61.029 ;
        RECT  215.982 60.471 216 60.489 ;
        RECT  215.982 59.931 216 59.949 ;
        RECT  215.982 59.391 216 59.409 ;
        RECT  215.982 58.851 216 58.869 ;
        RECT  215.982 58.311 216 58.329 ;
        RECT  215.982 57.771 216 57.789 ;
        RECT  215.982 57.231 216 57.249 ;
        RECT  215.982 56.691 216 56.709 ;
        RECT  215.982 56.151 216 56.169 ;
        RECT  215.982 55.611 216 55.629 ;
        RECT  215.982 55.071 216 55.089 ;
        RECT  215.982 54.531 216 54.549 ;
        RECT  215.982 53.991 216 54.009 ;
        RECT  215.982 53.451 216 53.469 ;
        RECT  215.982 52.911 216 52.929 ;
        RECT  215.982 52.371 216 52.389 ;
        RECT  215.982 51.831 216 51.849 ;
        RECT  215.982 51.291 216 51.309 ;
        RECT  215.982 50.751 216 50.769 ;
        RECT  215.982 50.211 216 50.229 ;
        RECT  215.982 49.671 216 49.689 ;
        RECT  215.982 49.131 216 49.149 ;
        RECT  215.982 48.591 216 48.609 ;
        RECT  215.982 48.051 216 48.069 ;
        RECT  215.982 47.511 216 47.529 ;
        RECT  215.982 46.971 216 46.989 ;
        RECT  215.982 46.431 216 46.449 ;
        RECT  215.982 45.891 216 45.909 ;
        RECT  215.982 45.351 216 45.369 ;
        RECT  215.982 44.811 216 44.829 ;
        RECT  215.982 44.271 216 44.289 ;
        RECT  215.982 43.731 216 43.749 ;
        RECT  215.982 43.191 216 43.209 ;
        RECT  215.982 42.651 216 42.669 ;
        RECT  215.982 42.111 216 42.129 ;
        RECT  215.982 41.571 216 41.589 ;
        RECT  215.982 41.031 216 41.049 ;
        RECT  215.982 40.491 216 40.509 ;
        RECT  215.982 39.951 216 39.969 ;
        RECT  215.982 39.411 216 39.429 ;
        RECT  215.982 38.871 216 38.889 ;
        RECT  215.982 38.331 216 38.349 ;
        RECT  215.982 37.791 216 37.809 ;
        RECT  215.982 37.251 216 37.269 ;
        RECT  215.982 36.711 216 36.729 ;
        RECT  215.982 36.171 216 36.189 ;
        RECT  215.982 35.631 216 35.649 ;
        RECT  215.982 35.091 216 35.109 ;
        RECT  215.982 34.551 216 34.569 ;
        RECT  215.982 34.011 216 34.029 ;
        RECT  215.982 33.471 216 33.489 ;
        RECT  215.982 32.931 216 32.949 ;
        RECT  215.982 32.391 216 32.409 ;
        RECT  215.982 31.851 216 31.869 ;
        RECT  215.982 31.311 216 31.329 ;
        RECT  215.982 30.771 216 30.789 ;
        RECT  215.982 30.231 216 30.249 ;
        RECT  215.982 29.691 216 29.709 ;
        RECT  215.982 29.151 216 29.169 ;
        RECT  215.982 28.611 216 28.629 ;
        RECT  215.982 28.071 216 28.089 ;
        RECT  215.982 27.531 216 27.549 ;
        RECT  215.982 26.991 216 27.009 ;
        RECT  215.982 26.451 216 26.469 ;
        RECT  215.982 25.911 216 25.929 ;
        RECT  215.982 25.371 216 25.389 ;
        RECT  215.982 24.831 216 24.849 ;
        RECT  215.982 24.291 216 24.309 ;
        RECT  215.982 23.751 216 23.769 ;
        RECT  215.982 23.211 216 23.229 ;
        RECT  215.982 22.671 216 22.689 ;
        RECT  215.982 22.131 216 22.149 ;
        RECT  215.982 21.591 216 21.609 ;
        RECT  215.982 21.051 216 21.069 ;
        RECT  215.982 20.511 216 20.529 ;
        RECT  215.982 19.971 216 19.989 ;
        RECT  215.982 19.431 216 19.449 ;
        RECT  215.982 18.891 216 18.909 ;
        RECT  215.982 18.351 216 18.369 ;
        RECT  215.982 17.811 216 17.829 ;
        RECT  215.982 17.271 216 17.289 ;
        RECT  215.982 16.731 216 16.749 ;
        RECT  215.982 16.191 216 16.209 ;
        RECT  215.982 15.651 216 15.669 ;
        RECT  215.982 15.111 216 15.129 ;
        RECT  215.982 14.571 216 14.589 ;
        RECT  215.982 14.031 216 14.049 ;
        RECT  215.982 13.491 216 13.509 ;
        RECT  215.982 12.951 216 12.969 ;
        RECT  215.982 12.411 216 12.429 ;
        RECT  215.982 11.871 216 11.889 ;
        RECT  215.982 11.331 216 11.349 ;
        RECT  215.982 10.791 216 10.809 ;
        RECT  215.982 10.251 216 10.269 ;
        RECT  215.982 9.711 216 9.729 ;
        RECT  215.982 9.171 216 9.189 ;
        RECT  215.982 8.631 216 8.649 ;
        RECT  215.982 8.091 216 8.109 ;
        RECT  215.982 7.551 216 7.569 ;
        RECT  215.982 7.011 216 7.029 ;
        RECT  215.982 6.471 216 6.489 ;
        RECT  215.982 5.931 216 5.949 ;
        RECT  215.982 5.391 216 5.409 ;
        RECT  215.982 4.851 216 4.869 ;
        RECT  215.982 4.311 216 4.329 ;
        RECT  215.982 3.771 216 3.789 ;
        RECT  215.982 3.231 216 3.249 ;
        RECT  215.982 2.691 216 2.709 ;
        RECT  215.982 2.151 216 2.169 ;
        RECT  215.982 1.611 216 1.629 ;
        RECT  215.982 1.071 216 1.089 ;
        RECT  215.982 0.531 216 0.549 ;
        RECT  215.982 215.451 216 215.469 ;
        RECT  0 215.451 0.018 215.469 ;
        RECT  215.982 214.911 216 214.929 ;
        RECT  0 214.911 0.018 214.929 ;
        RECT  215.982 214.371 216 214.389 ;
        RECT  0 214.371 0.018 214.389 ;
        RECT  215.982 213.831 216 213.849 ;
        RECT  0 213.831 0.018 213.849 ;
        RECT  215.982 213.291 216 213.309 ;
        RECT  0 213.291 0.018 213.309 ;
        RECT  215.982 212.751 216 212.769 ;
        RECT  0 212.751 0.018 212.769 ;
        RECT  215.982 212.211 216 212.229 ;
        RECT  0 212.211 0.018 212.229 ;
        RECT  215.982 211.671 216 211.689 ;
        RECT  0 211.671 0.018 211.689 ;
        RECT  215.982 211.131 216 211.149 ;
        RECT  0 211.131 0.018 211.149 ;
        RECT  215.982 210.591 216 210.609 ;
        RECT  0 210.591 0.018 210.609 ;
        RECT  215.982 210.051 216 210.069 ;
        RECT  0 210.051 0.018 210.069 ;
        RECT  215.982 209.511 216 209.529 ;
        RECT  0 209.511 0.018 209.529 ;
        RECT  215.982 208.971 216 208.989 ;
        RECT  0 208.971 0.018 208.989 ;
        RECT  215.982 208.431 216 208.449 ;
        RECT  0 208.431 0.018 208.449 ;
        RECT  215.982 207.891 216 207.909 ;
        RECT  0 207.891 0.018 207.909 ;
        RECT  215.982 207.351 216 207.369 ;
        RECT  0 207.351 0.018 207.369 ;
        RECT  215.982 206.811 216 206.829 ;
        RECT  0 206.811 0.018 206.829 ;
        RECT  215.982 206.271 216 206.289 ;
        RECT  0 206.271 0.018 206.289 ;
        RECT  215.982 205.731 216 205.749 ;
        RECT  0 205.731 0.018 205.749 ;
        RECT  215.982 205.191 216 205.209 ;
        RECT  0 205.191 0.018 205.209 ;
        RECT  215.982 204.651 216 204.669 ;
        RECT  0 204.651 0.018 204.669 ;
        RECT  215.982 204.111 216 204.129 ;
        RECT  0 204.111 0.018 204.129 ;
        RECT  215.982 203.571 216 203.589 ;
        RECT  0 203.571 0.018 203.589 ;
        RECT  215.982 203.031 216 203.049 ;
        RECT  0 203.031 0.018 203.049 ;
        RECT  215.982 202.491 216 202.509 ;
        RECT  0 202.491 0.018 202.509 ;
        RECT  215.982 201.951 216 201.969 ;
        RECT  0 201.951 0.018 201.969 ;
        RECT  215.982 201.411 216 201.429 ;
        RECT  0 201.411 0.018 201.429 ;
        RECT  215.982 200.871 216 200.889 ;
        RECT  0 200.871 0.018 200.889 ;
        RECT  215.982 200.331 216 200.349 ;
        RECT  0 200.331 0.018 200.349 ;
        RECT  215.982 199.791 216 199.809 ;
        RECT  0 199.791 0.018 199.809 ;
        RECT  215.982 199.251 216 199.269 ;
        RECT  0 199.251 0.018 199.269 ;
        RECT  215.982 198.711 216 198.729 ;
        RECT  0 198.711 0.018 198.729 ;
        RECT  215.982 198.171 216 198.189 ;
        RECT  0 198.171 0.018 198.189 ;
        RECT  215.982 197.631 216 197.649 ;
        RECT  0 197.631 0.018 197.649 ;
        RECT  215.982 197.091 216 197.109 ;
        RECT  0 197.091 0.018 197.109 ;
        RECT  215.982 196.551 216 196.569 ;
        RECT  0 196.551 0.018 196.569 ;
        RECT  215.982 196.011 216 196.029 ;
        RECT  0 196.011 0.018 196.029 ;
        RECT  215.982 195.471 216 195.489 ;
        RECT  0 195.471 0.018 195.489 ;
        RECT  215.982 194.931 216 194.949 ;
        RECT  0 194.931 0.018 194.949 ;
        RECT  215.982 194.391 216 194.409 ;
        RECT  0 194.391 0.018 194.409 ;
        RECT  215.982 193.851 216 193.869 ;
        RECT  0 193.851 0.018 193.869 ;
        RECT  215.982 193.311 216 193.329 ;
        RECT  0 193.311 0.018 193.329 ;
        RECT  215.982 192.771 216 192.789 ;
        RECT  0 192.771 0.018 192.789 ;
        RECT  215.982 192.231 216 192.249 ;
        RECT  0 192.231 0.018 192.249 ;
        RECT  215.982 191.691 216 191.709 ;
        RECT  0 191.691 0.018 191.709 ;
        RECT  215.982 191.151 216 191.169 ;
        RECT  0 191.151 0.018 191.169 ;
        RECT  215.982 190.611 216 190.629 ;
        RECT  0 190.611 0.018 190.629 ;
        RECT  215.982 190.071 216 190.089 ;
        RECT  0 190.071 0.018 190.089 ;
        RECT  215.982 189.531 216 189.549 ;
        RECT  0 189.531 0.018 189.549 ;
        RECT  215.982 188.991 216 189.009 ;
        RECT  0 188.991 0.018 189.009 ;
        RECT  215.982 188.451 216 188.469 ;
        RECT  0 188.451 0.018 188.469 ;
        RECT  215.982 187.911 216 187.929 ;
        RECT  0 187.911 0.018 187.929 ;
        RECT  215.982 187.371 216 187.389 ;
        RECT  0 187.371 0.018 187.389 ;
        RECT  215.982 186.831 216 186.849 ;
        RECT  0 186.831 0.018 186.849 ;
        RECT  215.982 186.291 216 186.309 ;
        RECT  0 186.291 0.018 186.309 ;
        RECT  215.982 185.751 216 185.769 ;
        RECT  0 185.751 0.018 185.769 ;
        RECT  215.982 185.211 216 185.229 ;
        RECT  0 185.211 0.018 185.229 ;
        RECT  215.982 184.671 216 184.689 ;
        RECT  0 184.671 0.018 184.689 ;
        RECT  215.982 184.131 216 184.149 ;
        RECT  0 184.131 0.018 184.149 ;
        RECT  215.982 183.591 216 183.609 ;
        RECT  0 183.591 0.018 183.609 ;
        RECT  215.982 183.051 216 183.069 ;
        RECT  0 183.051 0.018 183.069 ;
        RECT  215.982 182.511 216 182.529 ;
        RECT  0 182.511 0.018 182.529 ;
        RECT  215.982 181.971 216 181.989 ;
        RECT  0 181.971 0.018 181.989 ;
        RECT  215.982 181.431 216 181.449 ;
        RECT  0 181.431 0.018 181.449 ;
        RECT  215.982 180.891 216 180.909 ;
        RECT  0 180.891 0.018 180.909 ;
        RECT  215.982 180.351 216 180.369 ;
        RECT  0 180.351 0.018 180.369 ;
        RECT  215.982 179.811 216 179.829 ;
        RECT  0 179.811 0.018 179.829 ;
        RECT  215.982 179.271 216 179.289 ;
        RECT  0 179.271 0.018 179.289 ;
        RECT  215.982 178.731 216 178.749 ;
        RECT  0 178.731 0.018 178.749 ;
        RECT  215.982 178.191 216 178.209 ;
        RECT  0 178.191 0.018 178.209 ;
        RECT  215.982 177.651 216 177.669 ;
        RECT  0 177.651 0.018 177.669 ;
        RECT  215.982 177.111 216 177.129 ;
        RECT  0 177.111 0.018 177.129 ;
        RECT  215.982 176.571 216 176.589 ;
        RECT  0 176.571 0.018 176.589 ;
        RECT  215.982 176.031 216 176.049 ;
        RECT  0 176.031 0.018 176.049 ;
        RECT  215.982 175.491 216 175.509 ;
        RECT  0 175.491 0.018 175.509 ;
    END
  END VSS
  OBS
    LAYER RVTN ;
     RECT  174.852 0.54 216 0.675 ;
     RECT  174.852 0.945 216 1.215 ;
     RECT  174.852 1.485 216 1.755 ;
     RECT  174.852 2.025 216 2.295 ;
     RECT  174.852 2.565 216 2.835 ;
     RECT  174.852 3.105 216 3.375 ;
     RECT  174.852 3.645 216 3.915 ;
     RECT  174.852 4.185 216 4.455 ;
     RECT  174.852 4.725 216 4.995 ;
     RECT  174.852 5.265 216 5.535 ;
     RECT  174.852 5.805 216 6.075 ;
     RECT  174.852 6.345 216 6.615 ;
     RECT  174.852 6.885 216 7.155 ;
     RECT  174.852 7.425 216 7.695 ;
     RECT  174.852 7.965 216 8.235 ;
     RECT  174.852 8.505 216 8.775 ;
     RECT  174.852 9.045 216 9.315 ;
     RECT  174.852 9.585 216 9.855 ;
     RECT  174.852 10.125 216 10.395 ;
     RECT  174.852 10.665 216 10.935 ;
     RECT  174.852 11.205 216 11.475 ;
     RECT  174.852 11.745 216 12.015 ;
     RECT  174.852 12.285 216 12.555 ;
     RECT  174.852 12.825 216 13.095 ;
     RECT  174.852 13.365 216 13.635 ;
     RECT  174.852 13.905 216 14.175 ;
     RECT  174.852 14.445 216 14.715 ;
     RECT  174.852 14.985 216 15.255 ;
     RECT  174.852 15.525 216 15.795 ;
     RECT  174.852 16.065 216 16.335 ;
     RECT  174.852 16.605 216 16.875 ;
     RECT  174.852 17.145 216 17.415 ;
     RECT  174.852 17.685 216 17.955 ;
     RECT  174.852 18.225 216 18.495 ;
     RECT  174.852 18.765 216 19.035 ;
     RECT  174.852 19.305 216 19.575 ;
     RECT  174.852 19.845 216 20.115 ;
     RECT  174.852 20.385 216 20.655 ;
     RECT  174.852 20.925 216 21.195 ;
     RECT  174.852 21.465 216 21.735 ;
     RECT  174.852 22.005 216 22.275 ;
     RECT  174.852 22.545 216 22.815 ;
     RECT  174.852 23.085 216 23.355 ;
     RECT  174.852 23.625 216 23.895 ;
     RECT  174.852 24.165 216 24.435 ;
     RECT  174.852 24.705 216 24.975 ;
     RECT  174.852 25.245 216 25.515 ;
     RECT  174.852 25.785 216 26.055 ;
     RECT  174.852 26.325 216 26.595 ;
     RECT  174.852 26.865 216 27.135 ;
     RECT  174.852 27.405 216 27.675 ;
     RECT  174.852 27.945 216 28.215 ;
     RECT  174.852 28.485 216 28.755 ;
     RECT  174.852 29.025 216 29.295 ;
     RECT  174.852 29.565 216 29.835 ;
     RECT  174.852 30.105 216 30.375 ;
     RECT  174.852 30.645 216 30.915 ;
     RECT  174.852 31.185 216 31.455 ;
     RECT  174.852 31.725 216 31.995 ;
     RECT  174.852 32.265 216 32.535 ;
     RECT  174.852 32.805 216 33.075 ;
     RECT  174.852 33.345 216 33.615 ;
     RECT  174.852 33.885 216 34.155 ;
     RECT  174.852 34.425 216 34.695 ;
     RECT  174.852 34.965 216 35.235 ;
     RECT  174.852 35.505 216 35.775 ;
     RECT  174.852 36.045 216 36.315 ;
     RECT  174.852 36.585 216 36.855 ;
     RECT  174.852 37.125 216 37.395 ;
     RECT  174.852 37.665 216 37.935 ;
     RECT  174.852 38.205 216 38.475 ;
     RECT  174.852 38.745 216 39.015 ;
     RECT  174.852 39.285 216 39.555 ;
     RECT  174.852 39.825 216 40.095 ;
     RECT  174.852 40.365 216 40.635 ;
     RECT  174.852 40.905 216 41.175 ;
     RECT  174.852 41.445 216 41.715 ;
     RECT  174.852 41.985 216 42.255 ;
     RECT  174.852 42.525 216 42.795 ;
     RECT  174.852 43.065 216 43.335 ;
     RECT  174.852 43.605 216 43.875 ;
     RECT  174.852 44.145 216 44.415 ;
     RECT  174.852 44.685 216 44.955 ;
     RECT  174.852 45.225 216 45.495 ;
     RECT  174.852 45.765 216 46.035 ;
     RECT  174.852 46.305 216 46.575 ;
     RECT  174.852 46.845 216 47.115 ;
     RECT  174.852 47.385 216 47.655 ;
     RECT  174.852 47.925 216 48.195 ;
     RECT  174.852 48.465 216 48.735 ;
     RECT  174.852 49.005 216 49.275 ;
     RECT  174.852 49.545 216 49.815 ;
     RECT  174.852 50.085 216 50.355 ;
     RECT  174.852 50.625 216 50.895 ;
     RECT  174.852 51.165 216 51.435 ;
     RECT  174.852 51.705 216 51.975 ;
     RECT  174.852 52.245 216 52.515 ;
     RECT  174.852 52.785 216 53.055 ;
     RECT  174.852 53.325 216 53.595 ;
     RECT  174.852 53.865 216 54.135 ;
     RECT  174.852 54.405 216 54.675 ;
     RECT  174.852 54.945 216 55.215 ;
     RECT  174.852 55.485 216 55.755 ;
     RECT  174.852 56.025 216 56.295 ;
     RECT  174.852 56.565 216 56.835 ;
     RECT  174.852 57.105 216 57.375 ;
     RECT  174.852 57.645 216 57.915 ;
     RECT  174.852 58.185 216 58.455 ;
     RECT  174.852 58.725 216 58.995 ;
     RECT  174.852 59.265 216 59.535 ;
     RECT  174.852 59.805 216 60.075 ;
     RECT  174.852 60.345 216 60.615 ;
     RECT  174.852 60.885 216 61.155 ;
     RECT  174.852 61.425 216 61.695 ;
     RECT  174.852 61.965 216 62.235 ;
     RECT  174.852 62.505 216 62.775 ;
     RECT  174.852 63.045 216 63.315 ;
     RECT  174.852 63.585 216 63.855 ;
     RECT  174.852 64.125 216 64.395 ;
     RECT  174.852 64.665 216 64.935 ;
     RECT  174.852 65.205 216 65.475 ;
     RECT  174.852 65.745 216 66.015 ;
     RECT  174.852 66.285 216 66.555 ;
     RECT  174.852 66.825 216 67.095 ;
     RECT  174.852 67.365 216 67.635 ;
     RECT  174.852 67.905 216 68.175 ;
     RECT  174.852 68.445 216 68.715 ;
     RECT  174.852 68.985 216 69.255 ;
     RECT  174.852 69.525 216 69.795 ;
     RECT  174.852 70.065 216 70.335 ;
     RECT  174.852 70.605 216 70.875 ;
     RECT  174.852 71.145 216 71.415 ;
     RECT  174.852 71.685 216 71.955 ;
     RECT  174.852 72.225 216 72.495 ;
     RECT  174.852 72.765 216 73.035 ;
     RECT  174.852 73.305 216 73.575 ;
     RECT  174.852 73.845 216 74.115 ;
     RECT  174.852 74.385 216 74.655 ;
     RECT  174.852 74.925 216 75.195 ;
     RECT  174.852 75.465 216 75.735 ;
     RECT  174.852 76.005 216 76.275 ;
     RECT  174.852 76.545 216 76.815 ;
     RECT  174.852 77.085 216 77.355 ;
     RECT  174.852 77.625 216 77.895 ;
     RECT  174.852 78.165 216 78.435 ;
     RECT  174.852 78.705 216 78.975 ;
     RECT  174.852 79.245 216 79.515 ;
     RECT  174.852 79.785 216 80.055 ;
     RECT  174.852 80.325 216 80.595 ;
     RECT  174.852 80.865 216 81.135 ;
     RECT  174.852 81.405 216 81.675 ;
     RECT  174.852 81.945 216 82.215 ;
     RECT  174.852 82.485 216 82.755 ;
     RECT  174.852 83.025 216 83.295 ;
     RECT  174.852 83.565 216 83.835 ;
     RECT  174.852 84.105 216 84.375 ;
     RECT  174.852 84.645 216 84.915 ;
     RECT  174.852 85.185 216 85.455 ;
     RECT  174.852 85.725 216 85.995 ;
     RECT  174.852 86.265 216 86.535 ;
     RECT  174.852 86.805 216 87.075 ;
     RECT  174.852 87.345 216 87.615 ;
     RECT  174.852 87.885 216 88.155 ;
     RECT  174.852 88.425 216 88.695 ;
     RECT  174.852 88.965 216 89.235 ;
     RECT  174.852 89.505 216 89.775 ;
     RECT  174.852 90.045 216 90.315 ;
     RECT  174.852 90.585 216 90.855 ;
     RECT  174.852 91.125 216 91.395 ;
     RECT  174.852 91.665 216 91.935 ;
     RECT  174.852 92.205 216 92.475 ;
     RECT  174.852 92.745 216 93.015 ;
     RECT  174.852 93.285 216 93.555 ;
     RECT  174.852 93.825 216 94.095 ;
     RECT  174.852 94.365 216 94.635 ;
     RECT  174.852 94.905 216 95.175 ;
     RECT  174.852 95.445 216 95.715 ;
     RECT  174.852 95.985 216 96.255 ;
     RECT  174.852 96.525 216 96.795 ;
     RECT  174.852 97.065 216 97.335 ;
     RECT  174.852 97.605 216 97.875 ;
     RECT  174.852 98.145 216 98.415 ;
     RECT  174.852 98.685 216 98.955 ;
     RECT  174.852 99.225 216 99.495 ;
     RECT  174.852 99.765 216 100.035 ;
     RECT  174.852 100.305 216 100.575 ;
     RECT  174.852 100.845 216 101.115 ;
     RECT  174.852 101.385 216 101.655 ;
     RECT  174.852 101.925 216 102.195 ;
     RECT  174.852 102.465 216 102.735 ;
     RECT  174.852 103.005 216 103.275 ;
     RECT  174.852 103.545 216 103.815 ;
     RECT  174.852 104.085 216 104.355 ;
     RECT  174.852 104.625 216 104.895 ;
     RECT  174.852 105.165 216 105.435 ;
     RECT  174.852 105.705 216 105.975 ;
     RECT  174.852 106.245 216 106.515 ;
     RECT  174.852 106.785 216 107.055 ;
     RECT  174.852 107.325 216 107.595 ;
     RECT  174.852 107.865 216 108.135 ;
     RECT  174.852 108.405 216 108.675 ;
     RECT  174.852 108.945 216 109.215 ;
     RECT  174.852 109.485 216 109.755 ;
     RECT  174.852 110.025 216 110.295 ;
     RECT  174.852 110.565 216 110.835 ;
     RECT  174.852 111.105 216 111.375 ;
     RECT  174.852 111.645 216 111.915 ;
     RECT  174.852 112.185 216 112.455 ;
     RECT  174.852 112.725 216 112.995 ;
     RECT  174.852 113.265 216 113.535 ;
     RECT  174.852 113.805 216 114.075 ;
     RECT  174.852 114.345 216 114.615 ;
     RECT  174.852 114.885 216 115.155 ;
     RECT  174.852 115.425 216 115.695 ;
     RECT  174.852 115.965 216 116.235 ;
     RECT  174.852 116.505 216 116.775 ;
     RECT  174.852 117.045 216 117.315 ;
     RECT  174.852 117.585 216 117.855 ;
     RECT  174.852 118.125 216 118.395 ;
     RECT  174.852 118.665 216 118.935 ;
     RECT  174.852 119.205 216 119.475 ;
     RECT  174.852 119.745 216 120.015 ;
     RECT  174.852 120.285 216 120.555 ;
     RECT  174.852 120.825 216 121.095 ;
     RECT  174.852 121.365 216 121.635 ;
     RECT  174.852 121.905 216 122.175 ;
     RECT  174.852 122.445 216 122.715 ;
     RECT  174.852 122.985 216 123.255 ;
     RECT  174.852 123.525 216 123.795 ;
     RECT  174.852 124.065 216 124.335 ;
     RECT  174.852 124.605 216 124.875 ;
     RECT  174.852 125.145 216 125.415 ;
     RECT  174.852 125.685 216 125.955 ;
     RECT  174.852 126.225 216 126.495 ;
     RECT  174.852 126.765 216 127.035 ;
     RECT  174.852 127.305 216 127.575 ;
     RECT  174.852 127.845 216 128.115 ;
     RECT  174.852 128.385 216 128.655 ;
     RECT  174.852 128.925 216 129.195 ;
     RECT  174.852 129.465 216 129.735 ;
     RECT  174.852 130.005 216 130.275 ;
     RECT  174.852 130.545 216 130.815 ;
     RECT  174.852 131.085 216 131.355 ;
     RECT  174.852 131.625 216 131.895 ;
     RECT  174.852 132.165 216 132.435 ;
     RECT  174.852 132.705 216 132.975 ;
     RECT  174.852 133.245 216 133.515 ;
     RECT  174.852 133.785 216 134.055 ;
     RECT  174.852 134.325 216 134.595 ;
     RECT  174.852 134.865 216 135.135 ;
     RECT  174.852 135.405 216 135.675 ;
     RECT  174.852 135.945 216 136.215 ;
     RECT  174.852 136.485 216 136.755 ;
     RECT  174.852 137.025 216 137.295 ;
     RECT  174.852 137.565 216 137.835 ;
     RECT  174.852 138.105 216 138.375 ;
     RECT  174.852 138.645 216 138.915 ;
     RECT  174.852 139.185 216 139.455 ;
     RECT  174.852 139.725 216 139.995 ;
     RECT  174.852 140.265 216 140.535 ;
     RECT  174.852 140.805 216 141.075 ;
     RECT  174.852 141.345 216 141.615 ;
     RECT  174.852 141.885 216 142.155 ;
     RECT  174.852 142.425 216 142.695 ;
     RECT  174.852 142.965 216 143.235 ;
     RECT  174.852 143.505 216 143.775 ;
     RECT  174.852 144.045 216 144.315 ;
     RECT  174.852 144.585 216 144.855 ;
     RECT  174.852 145.125 216 145.395 ;
     RECT  174.852 145.665 216 145.935 ;
     RECT  174.852 146.205 216 146.475 ;
     RECT  174.852 146.745 216 147.015 ;
     RECT  174.852 147.285 216 147.555 ;
     RECT  174.852 147.825 216 148.095 ;
     RECT  174.852 148.365 216 148.635 ;
     RECT  174.852 148.905 216 149.175 ;
     RECT  174.852 149.445 216 149.715 ;
     RECT  174.852 149.985 216 150.255 ;
     RECT  174.852 150.525 216 150.795 ;
     RECT  174.852 151.065 216 151.335 ;
     RECT  174.852 151.605 216 151.875 ;
     RECT  174.852 152.145 216 152.415 ;
     RECT  174.852 152.685 216 152.955 ;
     RECT  174.852 153.225 216 153.495 ;
     RECT  174.852 153.765 216 154.035 ;
     RECT  174.852 154.305 216 154.575 ;
     RECT  174.852 154.845 216 155.115 ;
     RECT  174.852 155.385 216 155.655 ;
     RECT  174.852 155.925 216 156.195 ;
     RECT  174.852 156.465 216 156.735 ;
     RECT  174.852 157.005 216 157.275 ;
     RECT  174.852 157.545 216 157.815 ;
     RECT  174.852 158.085 216 158.355 ;
     RECT  174.852 158.625 216 158.895 ;
     RECT  174.852 159.165 216 159.435 ;
     RECT  174.852 159.705 216 159.975 ;
     RECT  174.852 160.245 216 160.515 ;
     RECT  174.852 160.785 216 161.055 ;
     RECT  174.852 161.325 216 161.595 ;
     RECT  174.852 161.865 216 162.135 ;
     RECT  174.852 162.405 216 162.675 ;
     RECT  174.852 162.945 216 163.215 ;
     RECT  174.852 163.485 216 163.755 ;
     RECT  174.852 164.025 216 164.295 ;
     RECT  174.852 164.565 216 164.835 ;
     RECT  174.852 165.105 216 165.375 ;
     RECT  174.852 165.645 216 165.915 ;
     RECT  174.852 166.185 216 166.455 ;
     RECT  174.852 166.725 216 166.995 ;
     RECT  174.852 167.265 216 167.535 ;
     RECT  174.852 167.805 216 168.075 ;
     RECT  174.852 168.345 216 168.615 ;
     RECT  174.852 168.885 216 169.155 ;
     RECT  174.852 169.425 216 169.695 ;
     RECT  174.852 169.965 216 170.235 ;
     RECT  174.852 170.505 216 170.775 ;
     RECT  174.852 171.045 216 171.315 ;
     RECT  174.852 171.585 216 171.855 ;
     RECT  174.852 172.125 216 172.395 ;
     RECT  174.852 172.665 216 172.935 ;
     RECT  174.852 173.205 216 173.475 ;
     RECT  174.852 173.745 216 174.015 ;
     RECT  174.852 174.285 216 174.555 ;
     RECT  174.852 174.825 216 175.095 ;
     RECT  174.852 175.365 216 175.5 ;
     RECT  0 175.5 216 175.635 ;
     RECT  0 175.905 216 176.175 ;
     RECT  0 176.445 216 176.715 ;
     RECT  0 176.985 216 177.255 ;
     RECT  0 177.525 216 177.795 ;
     RECT  0 178.065 216 178.335 ;
     RECT  0 178.605 216 178.875 ;
     RECT  0 179.145 216 179.415 ;
     RECT  0 179.685 216 179.955 ;
     RECT  0 180.225 216 180.495 ;
     RECT  0 180.765 216 181.035 ;
     RECT  0 181.305 216 181.575 ;
     RECT  0 181.845 216 182.115 ;
     RECT  0 182.385 216 182.655 ;
     RECT  0 182.925 216 183.195 ;
     RECT  0 183.465 216 183.735 ;
     RECT  0 184.005 216 184.275 ;
     RECT  0 184.545 216 184.815 ;
     RECT  0 185.085 216 185.355 ;
     RECT  0 185.625 216 185.895 ;
     RECT  0 186.165 216 186.435 ;
     RECT  0 186.705 216 186.975 ;
     RECT  0 187.245 216 187.515 ;
     RECT  0 187.785 216 188.055 ;
     RECT  0 188.325 216 188.595 ;
     RECT  0 188.865 216 189.135 ;
     RECT  0 189.405 216 189.675 ;
     RECT  0 189.945 216 190.215 ;
     RECT  0 190.485 216 190.755 ;
     RECT  0 191.025 216 191.295 ;
     RECT  0 191.565 216 191.835 ;
     RECT  0 192.105 216 192.375 ;
     RECT  0 192.645 216 192.915 ;
     RECT  0 193.185 216 193.455 ;
     RECT  0 193.725 216 193.995 ;
     RECT  0 194.265 216 194.535 ;
     RECT  0 194.805 216 195.075 ;
     RECT  0 195.345 216 195.615 ;
     RECT  0 195.885 216 196.155 ;
     RECT  0 196.425 216 196.695 ;
     RECT  0 196.965 216 197.235 ;
     RECT  0 197.505 216 197.775 ;
     RECT  0 198.045 216 198.315 ;
     RECT  0 198.585 216 198.855 ;
     RECT  0 199.125 216 199.395 ;
     RECT  0 199.665 216 199.935 ;
     RECT  0 200.205 216 200.475 ;
     RECT  0 200.745 216 201.015 ;
     RECT  0 201.285 216 201.555 ;
     RECT  0 201.825 216 202.095 ;
     RECT  0 202.365 216 202.635 ;
     RECT  0 202.905 216 203.175 ;
     RECT  0 203.445 216 203.715 ;
     RECT  0 203.985 216 204.255 ;
     RECT  0 204.525 216 204.795 ;
     RECT  0 205.065 216 205.335 ;
     RECT  0 205.605 216 205.875 ;
     RECT  0 206.145 216 206.415 ;
     RECT  0 206.685 216 206.955 ;
     RECT  0 207.225 216 207.495 ;
     RECT  0 207.765 216 208.035 ;
     RECT  0 208.305 216 208.575 ;
     RECT  0 208.845 216 209.115 ;
     RECT  0 209.385 216 209.655 ;
     RECT  0 209.925 216 210.195 ;
     RECT  0 210.465 216 210.735 ;
     RECT  0 211.005 216 211.275 ;
     RECT  0 211.545 216 211.815 ;
     RECT  0 212.085 216 212.355 ;
     RECT  0 212.625 216 212.895 ;
     RECT  0 213.165 216 213.435 ;
     RECT  0 213.705 216 213.975 ;
     RECT  0 214.245 216 214.515 ;
     RECT  0 214.785 216 215.055 ;
     RECT  0 215.325 216 215.46 ;
    LAYER RVTP ;
     RECT  174.852 0.675 216 0.945 ;
     RECT  174.852 1.215 216 1.485 ;
     RECT  174.852 1.755 216 2.025 ;
     RECT  174.852 2.295 216 2.565 ;
     RECT  174.852 2.835 216 3.105 ;
     RECT  174.852 3.375 216 3.645 ;
     RECT  174.852 3.915 216 4.185 ;
     RECT  174.852 4.455 216 4.725 ;
     RECT  174.852 4.995 216 5.265 ;
     RECT  174.852 5.535 216 5.805 ;
     RECT  174.852 6.075 216 6.345 ;
     RECT  174.852 6.615 216 6.885 ;
     RECT  174.852 7.155 216 7.425 ;
     RECT  174.852 7.695 216 7.965 ;
     RECT  174.852 8.235 216 8.505 ;
     RECT  174.852 8.775 216 9.045 ;
     RECT  174.852 9.315 216 9.585 ;
     RECT  174.852 9.855 216 10.125 ;
     RECT  174.852 10.395 216 10.665 ;
     RECT  174.852 10.935 216 11.205 ;
     RECT  174.852 11.475 216 11.745 ;
     RECT  174.852 12.015 216 12.285 ;
     RECT  174.852 12.555 216 12.825 ;
     RECT  174.852 13.095 216 13.365 ;
     RECT  174.852 13.635 216 13.905 ;
     RECT  174.852 14.175 216 14.445 ;
     RECT  174.852 14.715 216 14.985 ;
     RECT  174.852 15.255 216 15.525 ;
     RECT  174.852 15.795 216 16.065 ;
     RECT  174.852 16.335 216 16.605 ;
     RECT  174.852 16.875 216 17.145 ;
     RECT  174.852 17.415 216 17.685 ;
     RECT  174.852 17.955 216 18.225 ;
     RECT  174.852 18.495 216 18.765 ;
     RECT  174.852 19.035 216 19.305 ;
     RECT  174.852 19.575 216 19.845 ;
     RECT  174.852 20.115 216 20.385 ;
     RECT  174.852 20.655 216 20.925 ;
     RECT  174.852 21.195 216 21.465 ;
     RECT  174.852 21.735 216 22.005 ;
     RECT  174.852 22.275 216 22.545 ;
     RECT  174.852 22.815 216 23.085 ;
     RECT  174.852 23.355 216 23.625 ;
     RECT  174.852 23.895 216 24.165 ;
     RECT  174.852 24.435 216 24.705 ;
     RECT  174.852 24.975 216 25.245 ;
     RECT  174.852 25.515 216 25.785 ;
     RECT  174.852 26.055 216 26.325 ;
     RECT  174.852 26.595 216 26.865 ;
     RECT  174.852 27.135 216 27.405 ;
     RECT  174.852 27.675 216 27.945 ;
     RECT  174.852 28.215 216 28.485 ;
     RECT  174.852 28.755 216 29.025 ;
     RECT  174.852 29.295 216 29.565 ;
     RECT  174.852 29.835 216 30.105 ;
     RECT  174.852 30.375 216 30.645 ;
     RECT  174.852 30.915 216 31.185 ;
     RECT  174.852 31.455 216 31.725 ;
     RECT  174.852 31.995 216 32.265 ;
     RECT  174.852 32.535 216 32.805 ;
     RECT  174.852 33.075 216 33.345 ;
     RECT  174.852 33.615 216 33.885 ;
     RECT  174.852 34.155 216 34.425 ;
     RECT  174.852 34.695 216 34.965 ;
     RECT  174.852 35.235 216 35.505 ;
     RECT  174.852 35.775 216 36.045 ;
     RECT  174.852 36.315 216 36.585 ;
     RECT  174.852 36.855 216 37.125 ;
     RECT  174.852 37.395 216 37.665 ;
     RECT  174.852 37.935 216 38.205 ;
     RECT  174.852 38.475 216 38.745 ;
     RECT  174.852 39.015 216 39.285 ;
     RECT  174.852 39.555 216 39.825 ;
     RECT  174.852 40.095 216 40.365 ;
     RECT  174.852 40.635 216 40.905 ;
     RECT  174.852 41.175 216 41.445 ;
     RECT  174.852 41.715 216 41.985 ;
     RECT  174.852 42.255 216 42.525 ;
     RECT  174.852 42.795 216 43.065 ;
     RECT  174.852 43.335 216 43.605 ;
     RECT  174.852 43.875 216 44.145 ;
     RECT  174.852 44.415 216 44.685 ;
     RECT  174.852 44.955 216 45.225 ;
     RECT  174.852 45.495 216 45.765 ;
     RECT  174.852 46.035 216 46.305 ;
     RECT  174.852 46.575 216 46.845 ;
     RECT  174.852 47.115 216 47.385 ;
     RECT  174.852 47.655 216 47.925 ;
     RECT  174.852 48.195 216 48.465 ;
     RECT  174.852 48.735 216 49.005 ;
     RECT  174.852 49.275 216 49.545 ;
     RECT  174.852 49.815 216 50.085 ;
     RECT  174.852 50.355 216 50.625 ;
     RECT  174.852 50.895 216 51.165 ;
     RECT  174.852 51.435 216 51.705 ;
     RECT  174.852 51.975 216 52.245 ;
     RECT  174.852 52.515 216 52.785 ;
     RECT  174.852 53.055 216 53.325 ;
     RECT  174.852 53.595 216 53.865 ;
     RECT  174.852 54.135 216 54.405 ;
     RECT  174.852 54.675 216 54.945 ;
     RECT  174.852 55.215 216 55.485 ;
     RECT  174.852 55.755 216 56.025 ;
     RECT  174.852 56.295 216 56.565 ;
     RECT  174.852 56.835 216 57.105 ;
     RECT  174.852 57.375 216 57.645 ;
     RECT  174.852 57.915 216 58.185 ;
     RECT  174.852 58.455 216 58.725 ;
     RECT  174.852 58.995 216 59.265 ;
     RECT  174.852 59.535 216 59.805 ;
     RECT  174.852 60.075 216 60.345 ;
     RECT  174.852 60.615 216 60.885 ;
     RECT  174.852 61.155 216 61.425 ;
     RECT  174.852 61.695 216 61.965 ;
     RECT  174.852 62.235 216 62.505 ;
     RECT  174.852 62.775 216 63.045 ;
     RECT  174.852 63.315 216 63.585 ;
     RECT  174.852 63.855 216 64.125 ;
     RECT  174.852 64.395 216 64.665 ;
     RECT  174.852 64.935 216 65.205 ;
     RECT  174.852 65.475 216 65.745 ;
     RECT  174.852 66.015 216 66.285 ;
     RECT  174.852 66.555 216 66.825 ;
     RECT  174.852 67.095 216 67.365 ;
     RECT  174.852 67.635 216 67.905 ;
     RECT  174.852 68.175 216 68.445 ;
     RECT  174.852 68.715 216 68.985 ;
     RECT  174.852 69.255 216 69.525 ;
     RECT  174.852 69.795 216 70.065 ;
     RECT  174.852 70.335 216 70.605 ;
     RECT  174.852 70.875 216 71.145 ;
     RECT  174.852 71.415 216 71.685 ;
     RECT  174.852 71.955 216 72.225 ;
     RECT  174.852 72.495 216 72.765 ;
     RECT  174.852 73.035 216 73.305 ;
     RECT  174.852 73.575 216 73.845 ;
     RECT  174.852 74.115 216 74.385 ;
     RECT  174.852 74.655 216 74.925 ;
     RECT  174.852 75.195 216 75.465 ;
     RECT  174.852 75.735 216 76.005 ;
     RECT  174.852 76.275 216 76.545 ;
     RECT  174.852 76.815 216 77.085 ;
     RECT  174.852 77.355 216 77.625 ;
     RECT  174.852 77.895 216 78.165 ;
     RECT  174.852 78.435 216 78.705 ;
     RECT  174.852 78.975 216 79.245 ;
     RECT  174.852 79.515 216 79.785 ;
     RECT  174.852 80.055 216 80.325 ;
     RECT  174.852 80.595 216 80.865 ;
     RECT  174.852 81.135 216 81.405 ;
     RECT  174.852 81.675 216 81.945 ;
     RECT  174.852 82.215 216 82.485 ;
     RECT  174.852 82.755 216 83.025 ;
     RECT  174.852 83.295 216 83.565 ;
     RECT  174.852 83.835 216 84.105 ;
     RECT  174.852 84.375 216 84.645 ;
     RECT  174.852 84.915 216 85.185 ;
     RECT  174.852 85.455 216 85.725 ;
     RECT  174.852 85.995 216 86.265 ;
     RECT  174.852 86.535 216 86.805 ;
     RECT  174.852 87.075 216 87.345 ;
     RECT  174.852 87.615 216 87.885 ;
     RECT  174.852 88.155 216 88.425 ;
     RECT  174.852 88.695 216 88.965 ;
     RECT  174.852 89.235 216 89.505 ;
     RECT  174.852 89.775 216 90.045 ;
     RECT  174.852 90.315 216 90.585 ;
     RECT  174.852 90.855 216 91.125 ;
     RECT  174.852 91.395 216 91.665 ;
     RECT  174.852 91.935 216 92.205 ;
     RECT  174.852 92.475 216 92.745 ;
     RECT  174.852 93.015 216 93.285 ;
     RECT  174.852 93.555 216 93.825 ;
     RECT  174.852 94.095 216 94.365 ;
     RECT  174.852 94.635 216 94.905 ;
     RECT  174.852 95.175 216 95.445 ;
     RECT  174.852 95.715 216 95.985 ;
     RECT  174.852 96.255 216 96.525 ;
     RECT  174.852 96.795 216 97.065 ;
     RECT  174.852 97.335 216 97.605 ;
     RECT  174.852 97.875 216 98.145 ;
     RECT  174.852 98.415 216 98.685 ;
     RECT  174.852 98.955 216 99.225 ;
     RECT  174.852 99.495 216 99.765 ;
     RECT  174.852 100.035 216 100.305 ;
     RECT  174.852 100.575 216 100.845 ;
     RECT  174.852 101.115 216 101.385 ;
     RECT  174.852 101.655 216 101.925 ;
     RECT  174.852 102.195 216 102.465 ;
     RECT  174.852 102.735 216 103.005 ;
     RECT  174.852 103.275 216 103.545 ;
     RECT  174.852 103.815 216 104.085 ;
     RECT  174.852 104.355 216 104.625 ;
     RECT  174.852 104.895 216 105.165 ;
     RECT  174.852 105.435 216 105.705 ;
     RECT  174.852 105.975 216 106.245 ;
     RECT  174.852 106.515 216 106.785 ;
     RECT  174.852 107.055 216 107.325 ;
     RECT  174.852 107.595 216 107.865 ;
     RECT  174.852 108.135 216 108.405 ;
     RECT  174.852 108.675 216 108.945 ;
     RECT  174.852 109.215 216 109.485 ;
     RECT  174.852 109.755 216 110.025 ;
     RECT  174.852 110.295 216 110.565 ;
     RECT  174.852 110.835 216 111.105 ;
     RECT  174.852 111.375 216 111.645 ;
     RECT  174.852 111.915 216 112.185 ;
     RECT  174.852 112.455 216 112.725 ;
     RECT  174.852 112.995 216 113.265 ;
     RECT  174.852 113.535 216 113.805 ;
     RECT  174.852 114.075 216 114.345 ;
     RECT  174.852 114.615 216 114.885 ;
     RECT  174.852 115.155 216 115.425 ;
     RECT  174.852 115.695 216 115.965 ;
     RECT  174.852 116.235 216 116.505 ;
     RECT  174.852 116.775 216 117.045 ;
     RECT  174.852 117.315 216 117.585 ;
     RECT  174.852 117.855 216 118.125 ;
     RECT  174.852 118.395 216 118.665 ;
     RECT  174.852 118.935 216 119.205 ;
     RECT  174.852 119.475 216 119.745 ;
     RECT  174.852 120.015 216 120.285 ;
     RECT  174.852 120.555 216 120.825 ;
     RECT  174.852 121.095 216 121.365 ;
     RECT  174.852 121.635 216 121.905 ;
     RECT  174.852 122.175 216 122.445 ;
     RECT  174.852 122.715 216 122.985 ;
     RECT  174.852 123.255 216 123.525 ;
     RECT  174.852 123.795 216 124.065 ;
     RECT  174.852 124.335 216 124.605 ;
     RECT  174.852 124.875 216 125.145 ;
     RECT  174.852 125.415 216 125.685 ;
     RECT  174.852 125.955 216 126.225 ;
     RECT  174.852 126.495 216 126.765 ;
     RECT  174.852 127.035 216 127.305 ;
     RECT  174.852 127.575 216 127.845 ;
     RECT  174.852 128.115 216 128.385 ;
     RECT  174.852 128.655 216 128.925 ;
     RECT  174.852 129.195 216 129.465 ;
     RECT  174.852 129.735 216 130.005 ;
     RECT  174.852 130.275 216 130.545 ;
     RECT  174.852 130.815 216 131.085 ;
     RECT  174.852 131.355 216 131.625 ;
     RECT  174.852 131.895 216 132.165 ;
     RECT  174.852 132.435 216 132.705 ;
     RECT  174.852 132.975 216 133.245 ;
     RECT  174.852 133.515 216 133.785 ;
     RECT  174.852 134.055 216 134.325 ;
     RECT  174.852 134.595 216 134.865 ;
     RECT  174.852 135.135 216 135.405 ;
     RECT  174.852 135.675 216 135.945 ;
     RECT  174.852 136.215 216 136.485 ;
     RECT  174.852 136.755 216 137.025 ;
     RECT  174.852 137.295 216 137.565 ;
     RECT  174.852 137.835 216 138.105 ;
     RECT  174.852 138.375 216 138.645 ;
     RECT  174.852 138.915 216 139.185 ;
     RECT  174.852 139.455 216 139.725 ;
     RECT  174.852 139.995 216 140.265 ;
     RECT  174.852 140.535 216 140.805 ;
     RECT  174.852 141.075 216 141.345 ;
     RECT  174.852 141.615 216 141.885 ;
     RECT  174.852 142.155 216 142.425 ;
     RECT  174.852 142.695 216 142.965 ;
     RECT  174.852 143.235 216 143.505 ;
     RECT  174.852 143.775 216 144.045 ;
     RECT  174.852 144.315 216 144.585 ;
     RECT  174.852 144.855 216 145.125 ;
     RECT  174.852 145.395 216 145.665 ;
     RECT  174.852 145.935 216 146.205 ;
     RECT  174.852 146.475 216 146.745 ;
     RECT  174.852 147.015 216 147.285 ;
     RECT  174.852 147.555 216 147.825 ;
     RECT  174.852 148.095 216 148.365 ;
     RECT  174.852 148.635 216 148.905 ;
     RECT  174.852 149.175 216 149.445 ;
     RECT  174.852 149.715 216 149.985 ;
     RECT  174.852 150.255 216 150.525 ;
     RECT  174.852 150.795 216 151.065 ;
     RECT  174.852 151.335 216 151.605 ;
     RECT  174.852 151.875 216 152.145 ;
     RECT  174.852 152.415 216 152.685 ;
     RECT  174.852 152.955 216 153.225 ;
     RECT  174.852 153.495 216 153.765 ;
     RECT  174.852 154.035 216 154.305 ;
     RECT  174.852 154.575 216 154.845 ;
     RECT  174.852 155.115 216 155.385 ;
     RECT  174.852 155.655 216 155.925 ;
     RECT  174.852 156.195 216 156.465 ;
     RECT  174.852 156.735 216 157.005 ;
     RECT  174.852 157.275 216 157.545 ;
     RECT  174.852 157.815 216 158.085 ;
     RECT  174.852 158.355 216 158.625 ;
     RECT  174.852 158.895 216 159.165 ;
     RECT  174.852 159.435 216 159.705 ;
     RECT  174.852 159.975 216 160.245 ;
     RECT  174.852 160.515 216 160.785 ;
     RECT  174.852 161.055 216 161.325 ;
     RECT  174.852 161.595 216 161.865 ;
     RECT  174.852 162.135 216 162.405 ;
     RECT  174.852 162.675 216 162.945 ;
     RECT  174.852 163.215 216 163.485 ;
     RECT  174.852 163.755 216 164.025 ;
     RECT  174.852 164.295 216 164.565 ;
     RECT  174.852 164.835 216 165.105 ;
     RECT  174.852 165.375 216 165.645 ;
     RECT  174.852 165.915 216 166.185 ;
     RECT  174.852 166.455 216 166.725 ;
     RECT  174.852 166.995 216 167.265 ;
     RECT  174.852 167.535 216 167.805 ;
     RECT  174.852 168.075 216 168.345 ;
     RECT  174.852 168.615 216 168.885 ;
     RECT  174.852 169.155 216 169.425 ;
     RECT  174.852 169.695 216 169.965 ;
     RECT  174.852 170.235 216 170.505 ;
     RECT  174.852 170.775 216 171.045 ;
     RECT  174.852 171.315 216 171.585 ;
     RECT  174.852 171.855 216 172.125 ;
     RECT  174.852 172.395 216 172.665 ;
     RECT  174.852 172.935 216 173.205 ;
     RECT  174.852 173.475 216 173.745 ;
     RECT  174.852 174.015 216 174.285 ;
     RECT  174.852 174.555 216 174.825 ;
     RECT  174.852 175.095 216 175.365 ;
     RECT  0 175.635 216 175.905 ;
     RECT  0 176.175 216 176.445 ;
     RECT  0 176.715 216 176.985 ;
     RECT  0 177.255 216 177.525 ;
     RECT  0 177.795 216 178.065 ;
     RECT  0 178.335 216 178.605 ;
     RECT  0 178.875 216 179.145 ;
     RECT  0 179.415 216 179.685 ;
     RECT  0 179.955 216 180.225 ;
     RECT  0 180.495 216 180.765 ;
     RECT  0 181.035 216 181.305 ;
     RECT  0 181.575 216 181.845 ;
     RECT  0 182.115 216 182.385 ;
     RECT  0 182.655 216 182.925 ;
     RECT  0 183.195 216 183.465 ;
     RECT  0 183.735 216 184.005 ;
     RECT  0 184.275 216 184.545 ;
     RECT  0 184.815 216 185.085 ;
     RECT  0 185.355 216 185.625 ;
     RECT  0 185.895 216 186.165 ;
     RECT  0 186.435 216 186.705 ;
     RECT  0 186.975 216 187.245 ;
     RECT  0 187.515 216 187.785 ;
     RECT  0 188.055 216 188.325 ;
     RECT  0 188.595 216 188.865 ;
     RECT  0 189.135 216 189.405 ;
     RECT  0 189.675 216 189.945 ;
     RECT  0 190.215 216 190.485 ;
     RECT  0 190.755 216 191.025 ;
     RECT  0 191.295 216 191.565 ;
     RECT  0 191.835 216 192.105 ;
     RECT  0 192.375 216 192.645 ;
     RECT  0 192.915 216 193.185 ;
     RECT  0 193.455 216 193.725 ;
     RECT  0 193.995 216 194.265 ;
     RECT  0 194.535 216 194.805 ;
     RECT  0 195.075 216 195.345 ;
     RECT  0 195.615 216 195.885 ;
     RECT  0 196.155 216 196.425 ;
     RECT  0 196.695 216 196.965 ;
     RECT  0 197.235 216 197.505 ;
     RECT  0 197.775 216 198.045 ;
     RECT  0 198.315 216 198.585 ;
     RECT  0 198.855 216 199.125 ;
     RECT  0 199.395 216 199.665 ;
     RECT  0 199.935 216 200.205 ;
     RECT  0 200.475 216 200.745 ;
     RECT  0 201.015 216 201.285 ;
     RECT  0 201.555 216 201.825 ;
     RECT  0 202.095 216 202.365 ;
     RECT  0 202.635 216 202.905 ;
     RECT  0 203.175 216 203.445 ;
     RECT  0 203.715 216 203.985 ;
     RECT  0 204.255 216 204.525 ;
     RECT  0 204.795 216 205.065 ;
     RECT  0 205.335 216 205.605 ;
     RECT  0 205.875 216 206.145 ;
     RECT  0 206.415 216 206.685 ;
     RECT  0 206.955 216 207.225 ;
     RECT  0 207.495 216 207.765 ;
     RECT  0 208.035 216 208.305 ;
     RECT  0 208.575 216 208.845 ;
     RECT  0 209.115 216 209.385 ;
     RECT  0 209.655 216 209.925 ;
     RECT  0 210.195 216 210.465 ;
     RECT  0 210.735 216 211.005 ;
     RECT  0 211.275 216 211.545 ;
     RECT  0 211.815 216 212.085 ;
     RECT  0 212.355 216 212.625 ;
     RECT  0 212.895 216 213.165 ;
     RECT  0 213.435 216 213.705 ;
     RECT  0 213.975 216 214.245 ;
     RECT  0 214.515 216 214.785 ;
     RECT  0 215.055 216 215.325 ;
    LAYER M1 ;
     RECT  0.024 0.576 172.824 173.376 ;
     RECT  174.852 0.531 216 175.491 ;
     RECT  0 175.491 216 215.469 ;
    LAYER M2 ;
     RECT  0 175.491 40.459 215.469 ;
     RECT  40.459 175.446 107.843 215.469 ;
     RECT  0.024 0.576 172.824 173.376 ;
     RECT  172.824 85.536 174.852 85.554 ;
     RECT  172.824 103.32 174.852 103.734 ;
     RECT  107.843 175.491 174.852 215.469 ;
     RECT  174.852 0.531 216 215.469 ;
    LAYER M3 ;
     RECT  178.455 0.523 178.545 0.793 ;
     RECT  183.855 0.523 183.945 0.793 ;
     RECT  189.255 0.523 189.345 0.793 ;
     RECT  194.655 0.523 194.745 0.793 ;
     RECT  200.055 0.523 200.145 0.793 ;
     RECT  205.455 0.523 205.545 0.793 ;
     RECT  210.855 0.523 210.945 0.793 ;
     RECT  175.284 61.591 175.302 61.661 ;
     RECT  174.996 61.771 175.014 62.093 ;
     RECT  176.148 62.731 176.166 62.969 ;
     RECT  174.996 63.121 175.014 63.245 ;
     RECT  0.024 0.576 172.824 75.067 ;
     RECT  0.024 75.067 172.962 75.197 ;
     RECT  0.024 75.197 172.89 85.559 ;
     RECT  176.22 85.531 176.238 85.649 ;
     RECT  194.655 0.793 194.937 91.903 ;
     RECT  194.655 91.903 195.246 92.005 ;
     RECT  194.655 92.005 195.39 92.045 ;
     RECT  194.655 92.045 194.937 95.143 ;
     RECT  194.328 95.143 194.937 95.251 ;
     RECT  193.68 95.251 194.937 95.341 ;
     RECT  210.855 0.793 211.137 95.341 ;
     RECT  193.536 95.341 194.937 95.369 ;
     RECT  193.536 95.369 193.554 95.405 ;
     RECT  194.328 95.369 194.937 95.405 ;
     RECT  209.736 95.341 209.754 95.413 ;
     RECT  194.472 95.405 194.937 95.513 ;
     RECT  203.832 95.485 203.85 95.521 ;
     RECT  209.484 95.413 209.754 95.521 ;
     RECT  210.6 95.341 211.137 95.521 ;
     RECT  203.832 95.521 204.066 95.605 ;
     RECT  203.724 95.605 204.066 95.645 ;
     RECT  209.412 95.521 211.137 95.683 ;
     RECT  209.232 95.683 211.137 95.755 ;
     RECT  209.124 95.755 211.137 95.917 ;
     RECT  196.56 95.521 196.578 96.061 ;
     RECT  208.908 95.917 211.137 96.151 ;
     RECT  196.56 96.061 197.154 96.179 ;
     RECT  196.596 96.179 197.154 96.287 ;
     RECT  196.596 96.287 196.614 96.323 ;
     RECT  205.455 0.793 205.737 96.331 ;
     RECT  205.455 96.331 205.83 96.493 ;
     RECT  206.64 96.457 206.658 96.493 ;
     RECT  208.26 96.151 211.137 96.601 ;
     RECT  205.455 96.493 206.658 96.755 ;
     RECT  204.048 95.645 204.066 96.871 ;
     RECT  205.455 96.755 206.406 96.871 ;
     RECT  204.048 96.871 206.406 96.989 ;
     RECT  204.048 96.989 204.066 97.025 ;
     RECT  208.188 96.601 211.137 97.025 ;
     RECT  204.876 96.989 206.406 97.259 ;
     RECT  208.44 97.025 211.137 97.259 ;
     RECT  208.656 97.259 211.137 97.681 ;
     RECT  202.176 97.645 202.194 97.771 ;
     RECT  201.888 97.771 202.194 97.799 ;
     RECT  208.656 97.681 211.482 97.799 ;
     RECT  203.436 97.681 203.454 97.805 ;
     RECT  201.888 97.799 201.906 97.808 ;
     RECT  208.656 97.799 211.137 98.045 ;
     RECT  208.98 98.045 211.137 98.375 ;
     RECT  209.016 98.375 211.137 98.581 ;
     RECT  195.984 98.581 196.002 98.621 ;
     RECT  209.016 98.581 211.23 98.669 ;
     RECT  195.768 98.725 195.786 98.765 ;
     RECT  209.268 98.669 211.23 99.419 ;
     RECT  209.268 99.419 209.286 99.491 ;
     RECT  210.132 99.419 211.23 99.563 ;
     RECT  210.564 99.563 211.23 99.959 ;
     RECT  214.74 99.661 214.758 100.111 ;
     RECT  210.564 99.959 211.137 101.039 ;
     RECT  214.344 100.111 214.758 101.615 ;
     RECT  213.12 101.191 213.138 102.965 ;
     RECT  214.74 101.615 214.758 103.081 ;
     RECT  194.616 95.513 194.937 103.199 ;
     RECT  215.64 101.731 215.658 103.229 ;
     RECT  0.024 85.559 172.824 103.315 ;
     RECT  176.112 85.801 176.13 103.351 ;
     RECT  175.572 103.351 176.13 103.469 ;
     RECT  204.876 97.259 205.737 103.739 ;
     RECT  192.096 103.171 192.114 103.775 ;
     RECT  214.74 103.081 214.902 103.775 ;
     RECT  214.884 103.775 214.902 105.629 ;
     RECT  196.416 106.075 196.434 106.168 ;
     RECT  196.272 106.168 196.434 106.169 ;
     RECT  196.272 106.169 196.29 106.205 ;
     RECT  215.82 103.711 215.838 107.755 ;
     RECT  215.748 107.755 215.838 107.789 ;
     RECT  215.748 107.789 215.766 108.029 ;
     RECT  0.024 103.315 172.998 173.376 ;
     RECT  107.82 175.441 107.838 175.483 ;
     RECT  172.98 173.376 172.998 175.483 ;
     RECT  39.348 175.003 39.366 175.559 ;
     RECT  40.464 175.441 40.482 175.559 ;
     RECT  107.82 175.483 108.345 175.559 ;
     RECT  172.98 175.483 173.145 175.559 ;
     RECT  92.055 175.483 92.145 175.627 ;
     RECT  90.72 175.531 90.738 175.661 ;
     RECT  92.055 175.627 92.43 175.739 ;
     RECT  0.255 175.483 0.345 175.753 ;
     RECT  5.655 175.483 5.745 175.753 ;
     RECT  11.055 175.483 11.145 175.753 ;
     RECT  16.455 175.483 16.545 175.753 ;
     RECT  21.855 175.483 21.945 175.753 ;
     RECT  27.255 175.483 27.345 175.753 ;
     RECT  32.655 175.483 32.745 175.753 ;
     RECT  38.055 175.483 38.145 175.753 ;
     RECT  43.455 175.483 43.545 175.753 ;
     RECT  48.855 175.483 48.945 175.753 ;
     RECT  54.255 175.483 54.345 175.753 ;
     RECT  59.655 175.483 59.745 175.753 ;
     RECT  65.055 175.483 65.145 175.753 ;
     RECT  70.455 175.483 70.545 175.753 ;
     RECT  75.855 175.483 75.945 175.753 ;
     RECT  81.255 175.483 81.345 175.753 ;
     RECT  86.655 175.483 86.745 175.753 ;
     RECT  97.455 175.483 97.545 175.753 ;
     RECT  102.855 175.483 102.945 175.753 ;
     RECT  108.255 175.559 108.345 175.753 ;
     RECT  113.655 175.483 113.745 175.753 ;
     RECT  119.055 175.483 119.145 175.753 ;
     RECT  124.455 175.483 124.545 175.753 ;
     RECT  129.855 175.483 129.945 175.753 ;
     RECT  135.255 175.483 135.345 175.753 ;
     RECT  140.655 175.483 140.745 175.753 ;
     RECT  146.055 175.483 146.145 175.753 ;
     RECT  151.455 175.483 151.545 175.753 ;
     RECT  156.855 175.483 156.945 175.753 ;
     RECT  162.255 175.483 162.345 175.753 ;
     RECT  167.655 175.483 167.745 175.753 ;
     RECT  173.055 175.559 173.145 175.753 ;
     RECT  0.255 175.753 0.537 215.207 ;
     RECT  5.655 175.753 5.937 215.207 ;
     RECT  11.055 175.753 11.337 215.207 ;
     RECT  16.455 175.753 16.737 215.207 ;
     RECT  21.855 175.753 22.137 215.207 ;
     RECT  27.255 175.753 27.537 215.207 ;
     RECT  32.655 175.753 32.937 215.207 ;
     RECT  38.055 175.753 38.337 215.207 ;
     RECT  43.455 175.753 43.737 215.207 ;
     RECT  48.855 175.753 49.137 215.207 ;
     RECT  54.255 175.753 54.537 215.207 ;
     RECT  59.655 175.753 59.937 215.207 ;
     RECT  65.055 175.753 65.337 215.207 ;
     RECT  70.455 175.753 70.737 215.207 ;
     RECT  75.855 175.753 76.137 215.207 ;
     RECT  81.255 175.753 81.537 215.207 ;
     RECT  86.655 175.753 86.937 215.207 ;
     RECT  92.055 175.739 92.337 215.207 ;
     RECT  97.455 175.753 97.737 215.207 ;
     RECT  102.855 175.753 103.137 215.207 ;
     RECT  108.255 175.753 108.537 215.207 ;
     RECT  113.655 175.753 113.937 215.207 ;
     RECT  119.055 175.753 119.337 215.207 ;
     RECT  124.455 175.753 124.737 215.207 ;
     RECT  129.855 175.753 130.137 215.207 ;
     RECT  135.255 175.753 135.537 215.207 ;
     RECT  140.655 175.753 140.937 215.207 ;
     RECT  146.055 175.753 146.337 215.207 ;
     RECT  151.455 175.753 151.737 215.207 ;
     RECT  156.855 175.753 157.137 215.207 ;
     RECT  162.255 175.753 162.537 215.207 ;
     RECT  167.655 175.753 167.937 215.207 ;
     RECT  173.055 175.753 173.337 215.207 ;
     RECT  178.455 0.793 178.737 215.207 ;
     RECT  183.855 0.793 184.137 215.207 ;
     RECT  189.255 0.793 189.537 215.207 ;
     RECT  194.655 103.199 194.937 215.207 ;
     RECT  200.055 0.793 200.337 215.207 ;
     RECT  205.455 103.739 205.737 215.207 ;
     RECT  210.855 101.039 211.137 215.207 ;
     RECT  0.255 215.207 0.345 215.477 ;
     RECT  5.655 215.207 5.745 215.477 ;
     RECT  11.055 215.207 11.145 215.477 ;
     RECT  16.455 215.207 16.545 215.477 ;
     RECT  21.855 215.207 21.945 215.477 ;
     RECT  27.255 215.207 27.345 215.477 ;
     RECT  32.655 215.207 32.745 215.477 ;
     RECT  38.055 215.207 38.145 215.477 ;
     RECT  43.455 215.207 43.545 215.477 ;
     RECT  48.855 215.207 48.945 215.477 ;
     RECT  54.255 215.207 54.345 215.477 ;
     RECT  59.655 215.207 59.745 215.477 ;
     RECT  65.055 215.207 65.145 215.477 ;
     RECT  70.455 215.207 70.545 215.477 ;
     RECT  75.855 215.207 75.945 215.477 ;
     RECT  81.255 215.207 81.345 215.477 ;
     RECT  86.655 215.207 86.745 215.477 ;
     RECT  92.055 215.207 92.145 215.477 ;
     RECT  97.455 215.207 97.545 215.477 ;
     RECT  102.855 215.207 102.945 215.477 ;
     RECT  108.255 215.207 108.345 215.477 ;
     RECT  113.655 215.207 113.745 215.477 ;
     RECT  119.055 215.207 119.145 215.477 ;
     RECT  124.455 215.207 124.545 215.477 ;
     RECT  129.855 215.207 129.945 215.477 ;
     RECT  135.255 215.207 135.345 215.477 ;
     RECT  140.655 215.207 140.745 215.477 ;
     RECT  146.055 215.207 146.145 215.477 ;
     RECT  151.455 215.207 151.545 215.477 ;
     RECT  156.855 215.207 156.945 215.477 ;
     RECT  162.255 215.207 162.345 215.477 ;
     RECT  167.655 215.207 167.745 215.477 ;
     RECT  173.055 215.207 173.145 215.477 ;
     RECT  178.455 215.207 178.545 215.477 ;
     RECT  183.855 215.207 183.945 215.477 ;
     RECT  189.255 215.207 189.345 215.477 ;
     RECT  194.655 215.207 194.745 215.477 ;
     RECT  200.055 215.207 200.145 215.477 ;
     RECT  205.455 215.207 205.545 215.477 ;
     RECT  210.855 215.207 210.945 215.477 ;
    LAYER M4 ;
     RECT  0.037 100.8 0.096 100.824 ;
     RECT  0.248 175.488 0.352 215.472 ;
     RECT  0.352 175.758 0.544 215.202 ;
     RECT  5.648 175.488 5.752 215.472 ;
     RECT  5.752 175.758 5.944 215.202 ;
     RECT  11.048 175.488 11.152 215.472 ;
     RECT  11.152 175.758 11.344 215.202 ;
     RECT  16.448 175.488 16.552 215.472 ;
     RECT  16.552 175.758 16.744 215.202 ;
     RECT  21.848 175.488 21.952 215.472 ;
     RECT  21.952 175.758 22.144 215.202 ;
     RECT  27.248 175.488 27.352 215.472 ;
     RECT  27.352 175.758 27.544 215.202 ;
     RECT  32.648 175.488 32.752 215.472 ;
     RECT  32.752 175.758 32.944 215.202 ;
     RECT  38.048 175.488 38.152 215.472 ;
     RECT  38.152 175.758 38.344 215.202 ;
     RECT  39.337 175.008 39.421 175.032 ;
     RECT  43.448 175.488 43.552 215.472 ;
     RECT  43.552 175.758 43.744 215.202 ;
     RECT  48.848 175.488 48.952 215.472 ;
     RECT  48.952 175.758 49.144 215.202 ;
     RECT  54.248 175.488 54.352 215.472 ;
     RECT  54.352 175.758 54.544 215.202 ;
     RECT  59.648 175.488 59.752 215.472 ;
     RECT  59.752 175.758 59.944 215.202 ;
     RECT  65.048 175.488 65.152 215.472 ;
     RECT  65.152 175.758 65.344 215.202 ;
     RECT  70.448 175.488 70.552 215.472 ;
     RECT  70.552 175.758 70.744 215.202 ;
     RECT  75.848 175.488 75.952 215.472 ;
     RECT  75.952 175.758 76.144 215.202 ;
     RECT  81.248 175.488 81.352 215.472 ;
     RECT  81.352 175.758 81.544 215.202 ;
     RECT  86.648 175.488 86.752 215.472 ;
     RECT  86.752 175.758 86.944 215.202 ;
     RECT  90.709 175.632 90.793 175.656 ;
     RECT  92.048 175.488 92.152 215.472 ;
     RECT  92.152 175.632 92.344 215.202 ;
     RECT  92.344 175.632 92.441 175.656 ;
     RECT  97.448 175.488 97.552 215.472 ;
     RECT  97.552 175.758 97.744 215.202 ;
     RECT  102.848 175.488 102.952 215.472 ;
     RECT  102.952 175.758 103.144 215.202 ;
     RECT  108.248 175.488 108.352 215.472 ;
     RECT  108.352 175.758 108.544 215.202 ;
     RECT  113.648 175.488 113.752 215.472 ;
     RECT  113.752 175.758 113.944 215.202 ;
     RECT  119.048 175.488 119.152 215.472 ;
     RECT  119.152 175.758 119.344 215.202 ;
     RECT  124.448 175.488 124.552 215.472 ;
     RECT  124.552 175.758 124.744 215.202 ;
     RECT  129.848 175.488 129.952 215.472 ;
     RECT  129.952 175.758 130.144 215.202 ;
     RECT  135.248 175.488 135.352 215.472 ;
     RECT  135.352 175.758 135.544 215.202 ;
     RECT  140.648 175.488 140.752 215.472 ;
     RECT  140.752 175.758 140.944 215.202 ;
     RECT  146.048 175.488 146.152 215.472 ;
     RECT  146.152 175.758 146.344 215.202 ;
     RECT  151.448 175.488 151.552 215.472 ;
     RECT  151.552 175.758 151.744 215.202 ;
     RECT  156.848 175.488 156.952 215.472 ;
     RECT  156.952 175.758 157.144 215.202 ;
     RECT  162.248 175.488 162.352 215.472 ;
     RECT  162.352 175.758 162.544 215.202 ;
     RECT  167.648 175.488 167.752 215.472 ;
     RECT  167.752 175.758 167.944 215.202 ;
     RECT  0.096 0.576 172.752 173.376 ;
     RECT  172.752 62.784 172.931 62.808 ;
     RECT  172.752 87.36 172.931 87.384 ;
     RECT  172.752 99.648 172.931 99.672 ;
     RECT  172.752 111.936 172.931 111.96 ;
     RECT  172.752 75.072 172.973 75.192 ;
     RECT  172.752 124.128 172.973 124.248 ;
     RECT  173.048 175.488 173.152 215.472 ;
     RECT  173.152 175.758 173.344 215.202 ;
     RECT  174.985 63.216 175.069 63.24 ;
     RECT  174.985 62.064 175.229 62.088 ;
     RECT  175.229 61.632 175.313 62.088 ;
     RECT  175.313 62.064 175.523 62.088 ;
     RECT  176.137 62.736 176.221 62.76 ;
     RECT  178.448 0.528 178.552 215.472 ;
     RECT  178.552 0.798 178.744 215.202 ;
     RECT  183.848 0.528 183.952 215.472 ;
     RECT  183.952 0.798 184.144 215.202 ;
     RECT  189.248 0.528 189.352 215.472 ;
     RECT  189.352 0.798 189.544 215.202 ;
     RECT  193.525 95.376 194.648 95.4 ;
     RECT  194.648 0.528 194.752 215.472 ;
     RECT  194.752 0.798 194.944 215.202 ;
     RECT  194.944 91.92 195.257 92.04 ;
     RECT  195.257 92.016 195.436 92.04 ;
     RECT  194.944 98.736 195.82 98.76 ;
     RECT  195.973 98.592 196.067 98.616 ;
     RECT  196.069 106.176 196.301 106.2 ;
     RECT  196.405 106.08 196.489 106.104 ;
     RECT  196.549 96.288 196.636 96.312 ;
     RECT  200.048 0.528 200.152 215.472 ;
     RECT  200.152 0.798 200.344 215.202 ;
     RECT  201.781 97.776 201.917 97.8 ;
     RECT  203.381 97.776 203.465 97.8 ;
     RECT  203.669 95.616 203.891 95.64 ;
     RECT  205.333 97.824 205.448 97.848 ;
     RECT  205.448 0.528 205.552 215.472 ;
     RECT  205.552 0.798 205.744 215.202 ;
     RECT  205.744 96.336 205.885 96.36 ;
     RECT  208.885 96.24 208.972 96.264 ;
     RECT  208.645 97.536 209.221 98.664 ;
     RECT  209.221 97.008 209.473 98.664 ;
     RECT  209.473 97.008 209.545 98.904 ;
     RECT  209.545 97.008 210.193 98.952 ;
     RECT  210.193 96.72 210.848 98.952 ;
     RECT  210.848 0.528 210.952 215.472 ;
     RECT  210.952 0.798 211.144 215.202 ;
     RECT  211.144 98.88 211.205 98.904 ;
     RECT  214.885 96 215.82 96.024 ;
     RECT  214.885 98.4 215.82 98.424 ;
     RECT  214.885 100.8 215.82 100.824 ;
     RECT  215.629 103.2 215.82 103.224 ;
     RECT  214.873 105.6 215.82 105.624 ;
     RECT  215.737 107.76 215.82 108.024 ;
     RECT  215.82 107.76 215.849 107.784 ;
    LAYER M5 ;
     RECT  178.44 0.517 178.56 0.787 ;
     RECT  183.84 0.517 183.96 0.787 ;
     RECT  189.24 0.517 189.36 0.787 ;
     RECT  194.64 0.517 194.76 0.787 ;
     RECT  200.04 0.517 200.16 0.787 ;
     RECT  205.44 0.517 205.56 0.787 ;
     RECT  210.84 0.517 210.96 0.787 ;
     RECT  0.456 0.96 0.576 0.996 ;
     RECT  5.856 0.96 5.976 0.996 ;
     RECT  11.256 0.96 11.376 0.996 ;
     RECT  16.656 0.96 16.776 0.996 ;
     RECT  22.056 0.96 22.176 0.996 ;
     RECT  27.456 0.96 27.576 0.996 ;
     RECT  32.856 0.96 32.976 0.996 ;
     RECT  38.256 0.96 38.376 0.996 ;
     RECT  43.656 0.96 43.776 0.996 ;
     RECT  49.056 0.96 49.176 0.996 ;
     RECT  54.456 0.96 54.576 0.996 ;
     RECT  59.856 0.96 59.976 0.996 ;
     RECT  65.256 0.96 65.376 0.996 ;
     RECT  70.656 0.96 70.776 0.996 ;
     RECT  76.056 0.96 76.176 0.996 ;
     RECT  81.456 0.96 81.576 0.996 ;
     RECT  86.856 0.96 86.976 0.996 ;
     RECT  92.256 0.96 92.376 0.996 ;
     RECT  97.656 0.96 97.776 0.996 ;
     RECT  103.056 0.96 103.176 0.996 ;
     RECT  108.456 0.96 108.576 0.996 ;
     RECT  113.856 0.96 113.976 0.996 ;
     RECT  119.256 0.96 119.376 0.996 ;
     RECT  124.656 0.96 124.776 0.996 ;
     RECT  130.056 0.96 130.176 0.996 ;
     RECT  135.456 0.96 135.576 0.996 ;
     RECT  140.856 0.96 140.976 0.996 ;
     RECT  146.256 0.96 146.376 0.996 ;
     RECT  151.656 0.96 151.776 0.996 ;
     RECT  157.056 0.96 157.176 0.996 ;
     RECT  162.456 0.96 162.576 0.996 ;
     RECT  167.856 0.96 167.976 0.996 ;
     RECT  175.248 61.621 175.272 61.705 ;
     RECT  175.488 62.053 175.512 62.137 ;
     RECT  176.16 62.709 176.184 62.797 ;
     RECT  172.896 62.709 172.92 62.819 ;
     RECT  175.008 63.205 175.032 63.289 ;
     RECT  172.896 87.221 172.92 87.395 ;
     RECT  194.64 0.787 194.952 91.871 ;
     RECT  194.64 91.871 195.048 91.987 ;
     RECT  194.64 91.987 195.384 92.075 ;
     RECT  194.64 92.075 194.952 95.327 ;
     RECT  193.776 95.327 194.952 95.411 ;
     RECT  203.712 95.571 203.88 95.659 ;
     RECT  214.896 95.989 214.92 96.073 ;
     RECT  205.44 0.787 205.752 96.245 ;
     RECT  208.896 96.211 208.92 96.299 ;
     RECT  196.56 95.349 196.584 96.323 ;
     RECT  205.44 96.245 205.848 96.371 ;
     RECT  205.44 96.371 205.752 97.781 ;
     RECT  201.792 97.765 201.816 97.849 ;
     RECT  203.424 97.765 203.448 97.849 ;
     RECT  205.344 97.781 205.752 97.869 ;
     RECT  214.896 98.389 214.92 98.603 ;
     RECT  196.032 98.543 196.056 98.627 ;
     RECT  208.656 98.005 208.68 98.675 ;
     RECT  194.64 95.411 194.952 98.725 ;
     RECT  172.896 99.603 172.92 99.691 ;
     RECT  194.64 98.725 195.768 99.691 ;
     RECT  0.264 0.996 0.576 100.789 ;
     RECT  0.048 100.789 0.576 100.873 ;
     RECT  214.896 100.789 214.92 100.873 ;
     RECT  0.264 100.873 0.576 105.555 ;
     RECT  0.144 105.555 0.576 105.643 ;
     RECT  196.416 106.031 196.44 106.115 ;
     RECT  196.08 106.165 196.104 106.249 ;
     RECT  172.896 111.861 172.92 111.971 ;
     RECT  0.264 105.643 0.576 172.32 ;
     RECT  5.664 0.996 5.976 172.32 ;
     RECT  11.064 0.996 11.376 172.32 ;
     RECT  16.464 0.996 16.776 172.32 ;
     RECT  21.864 0.996 22.176 172.32 ;
     RECT  27.264 0.996 27.576 172.32 ;
     RECT  32.664 0.996 32.976 172.32 ;
     RECT  38.064 0.996 38.376 172.32 ;
     RECT  43.464 0.996 43.776 172.32 ;
     RECT  48.864 0.996 49.176 172.32 ;
     RECT  54.264 0.996 54.576 172.32 ;
     RECT  59.664 0.996 59.976 172.32 ;
     RECT  65.064 0.996 65.376 172.32 ;
     RECT  70.464 0.996 70.776 172.32 ;
     RECT  75.864 0.996 76.176 172.32 ;
     RECT  81.264 0.996 81.576 172.32 ;
     RECT  86.664 0.996 86.976 172.32 ;
     RECT  92.064 0.996 92.376 172.32 ;
     RECT  97.464 0.996 97.776 172.32 ;
     RECT  102.864 0.996 103.176 172.32 ;
     RECT  108.264 0.996 108.576 172.32 ;
     RECT  113.664 0.996 113.976 172.32 ;
     RECT  119.064 0.996 119.376 172.32 ;
     RECT  124.464 0.996 124.776 172.32 ;
     RECT  129.864 0.996 130.176 172.32 ;
     RECT  135.264 0.996 135.576 172.32 ;
     RECT  140.664 0.996 140.976 172.32 ;
     RECT  146.064 0.996 146.376 172.32 ;
     RECT  151.464 0.996 151.776 172.32 ;
     RECT  156.864 0.996 157.176 172.32 ;
     RECT  162.264 0.996 162.576 172.32 ;
     RECT  167.664 0.996 167.976 172.32 ;
     RECT  0.456 172.32 0.576 173.088 ;
     RECT  5.856 172.32 5.976 173.088 ;
     RECT  11.256 172.32 11.376 173.088 ;
     RECT  16.656 172.32 16.776 173.088 ;
     RECT  22.056 172.32 22.176 173.088 ;
     RECT  27.456 172.32 27.576 173.088 ;
     RECT  32.856 172.32 32.976 173.088 ;
     RECT  38.256 172.32 38.376 173.088 ;
     RECT  43.656 172.32 43.776 173.088 ;
     RECT  49.056 172.32 49.176 173.088 ;
     RECT  54.456 172.32 54.576 173.088 ;
     RECT  59.856 172.32 59.976 173.088 ;
     RECT  65.256 172.32 65.376 173.088 ;
     RECT  70.656 172.32 70.776 173.088 ;
     RECT  76.056 172.32 76.176 173.088 ;
     RECT  81.456 172.32 81.576 173.088 ;
     RECT  86.856 172.32 86.976 173.088 ;
     RECT  92.256 172.32 92.376 173.088 ;
     RECT  97.656 172.32 97.776 173.088 ;
     RECT  103.056 172.32 103.176 173.088 ;
     RECT  108.456 172.32 108.576 173.088 ;
     RECT  113.856 172.32 113.976 173.088 ;
     RECT  119.256 172.32 119.376 173.088 ;
     RECT  124.656 172.32 124.776 173.088 ;
     RECT  130.056 172.32 130.176 173.088 ;
     RECT  135.456 172.32 135.576 173.088 ;
     RECT  140.856 172.32 140.976 173.088 ;
     RECT  146.256 172.32 146.376 173.088 ;
     RECT  151.656 172.32 151.776 173.088 ;
     RECT  157.056 172.32 157.176 173.088 ;
     RECT  162.456 172.32 162.576 173.088 ;
     RECT  167.856 172.32 167.976 173.088 ;
     RECT  39.36 105.589 39.384 175.043 ;
     RECT  90.72 175.477 90.744 175.667 ;
     RECT  92.04 175.477 92.424 175.667 ;
     RECT  0.24 175.477 0.36 175.747 ;
     RECT  5.64 175.477 5.76 175.747 ;
     RECT  11.04 175.477 11.16 175.747 ;
     RECT  16.44 175.477 16.56 175.747 ;
     RECT  21.84 175.477 21.96 175.747 ;
     RECT  27.24 175.477 27.36 175.747 ;
     RECT  32.64 175.477 32.76 175.747 ;
     RECT  38.04 175.477 38.16 175.747 ;
     RECT  43.44 175.477 43.56 175.747 ;
     RECT  48.84 175.477 48.96 175.747 ;
     RECT  54.24 175.477 54.36 175.747 ;
     RECT  59.64 175.477 59.76 175.747 ;
     RECT  65.04 175.477 65.16 175.747 ;
     RECT  70.44 175.477 70.56 175.747 ;
     RECT  75.84 175.477 75.96 175.747 ;
     RECT  81.24 175.477 81.36 175.747 ;
     RECT  86.64 175.477 86.76 175.747 ;
     RECT  97.44 175.477 97.56 175.747 ;
     RECT  102.84 175.477 102.96 175.747 ;
     RECT  108.24 175.477 108.36 175.747 ;
     RECT  113.64 175.477 113.76 175.747 ;
     RECT  119.04 175.477 119.16 175.747 ;
     RECT  124.44 175.477 124.56 175.747 ;
     RECT  129.84 175.477 129.96 175.747 ;
     RECT  135.24 175.477 135.36 175.747 ;
     RECT  140.64 175.477 140.76 175.747 ;
     RECT  146.04 175.477 146.16 175.747 ;
     RECT  151.44 175.477 151.56 175.747 ;
     RECT  156.84 175.477 156.96 175.747 ;
     RECT  162.24 175.477 162.36 175.747 ;
     RECT  167.64 175.477 167.76 175.747 ;
     RECT  173.04 175.477 173.16 175.747 ;
     RECT  0.24 175.747 0.552 215.213 ;
     RECT  5.64 175.747 5.952 215.213 ;
     RECT  11.04 175.747 11.352 215.213 ;
     RECT  16.44 175.747 16.752 215.213 ;
     RECT  21.84 175.747 22.152 215.213 ;
     RECT  27.24 175.747 27.552 215.213 ;
     RECT  32.64 175.747 32.952 215.213 ;
     RECT  38.04 175.747 38.352 215.213 ;
     RECT  43.44 175.747 43.752 215.213 ;
     RECT  48.84 175.747 49.152 215.213 ;
     RECT  54.24 175.747 54.552 215.213 ;
     RECT  59.64 175.747 59.952 215.213 ;
     RECT  65.04 175.747 65.352 215.213 ;
     RECT  70.44 175.747 70.752 215.213 ;
     RECT  75.84 175.747 76.152 215.213 ;
     RECT  81.24 175.747 81.552 215.213 ;
     RECT  86.64 175.747 86.952 215.213 ;
     RECT  92.04 175.667 92.352 215.213 ;
     RECT  97.44 175.747 97.752 215.213 ;
     RECT  102.84 175.747 103.152 215.213 ;
     RECT  108.24 175.747 108.552 215.213 ;
     RECT  113.64 175.747 113.952 215.213 ;
     RECT  119.04 175.747 119.352 215.213 ;
     RECT  124.44 175.747 124.752 215.213 ;
     RECT  129.84 175.747 130.152 215.213 ;
     RECT  135.24 175.747 135.552 215.213 ;
     RECT  140.64 175.747 140.952 215.213 ;
     RECT  146.04 175.747 146.352 215.213 ;
     RECT  151.44 175.747 151.752 215.213 ;
     RECT  156.84 175.747 157.152 215.213 ;
     RECT  162.24 175.747 162.552 215.213 ;
     RECT  167.64 175.747 167.952 215.213 ;
     RECT  173.04 175.747 173.352 215.213 ;
     RECT  178.44 0.787 178.752 215.213 ;
     RECT  183.84 0.787 184.152 215.213 ;
     RECT  189.24 0.787 189.552 215.213 ;
     RECT  194.64 99.691 194.952 215.213 ;
     RECT  200.04 0.787 200.352 215.213 ;
     RECT  205.44 97.869 205.752 215.213 ;
     RECT  210.84 0.787 211.152 215.213 ;
     RECT  0.24 215.213 0.36 215.483 ;
     RECT  5.64 215.213 5.76 215.483 ;
     RECT  11.04 215.213 11.16 215.483 ;
     RECT  16.44 215.213 16.56 215.483 ;
     RECT  21.84 215.213 21.96 215.483 ;
     RECT  27.24 215.213 27.36 215.483 ;
     RECT  32.64 215.213 32.76 215.483 ;
     RECT  38.04 215.213 38.16 215.483 ;
     RECT  43.44 215.213 43.56 215.483 ;
     RECT  48.84 215.213 48.96 215.483 ;
     RECT  54.24 215.213 54.36 215.483 ;
     RECT  59.64 215.213 59.76 215.483 ;
     RECT  65.04 215.213 65.16 215.483 ;
     RECT  70.44 215.213 70.56 215.483 ;
     RECT  75.84 215.213 75.96 215.483 ;
     RECT  81.24 215.213 81.36 215.483 ;
     RECT  86.64 215.213 86.76 215.483 ;
     RECT  92.04 215.213 92.16 215.483 ;
     RECT  97.44 215.213 97.56 215.483 ;
     RECT  102.84 215.213 102.96 215.483 ;
     RECT  108.24 215.213 108.36 215.483 ;
     RECT  113.64 215.213 113.76 215.483 ;
     RECT  119.04 215.213 119.16 215.483 ;
     RECT  124.44 215.213 124.56 215.483 ;
     RECT  129.84 215.213 129.96 215.483 ;
     RECT  135.24 215.213 135.36 215.483 ;
     RECT  140.64 215.213 140.76 215.483 ;
     RECT  146.04 215.213 146.16 215.483 ;
     RECT  151.44 215.213 151.56 215.483 ;
     RECT  156.84 215.213 156.96 215.483 ;
     RECT  162.24 215.213 162.36 215.483 ;
     RECT  167.64 215.213 167.76 215.483 ;
     RECT  173.04 215.213 173.16 215.483 ;
     RECT  178.44 215.213 178.56 215.483 ;
     RECT  183.84 215.213 183.96 215.483 ;
     RECT  189.24 215.213 189.36 215.483 ;
     RECT  194.64 215.213 194.76 215.483 ;
     RECT  200.04 215.213 200.16 215.483 ;
     RECT  205.44 215.213 205.56 215.483 ;
     RECT  210.84 215.213 210.96 215.483 ;
    LAYER M6 ;
     RECT  0 173.796 0.053 174.66 ;
     RECT  0.037 100.8 0.107 100.832 ;
     RECT  0 103.596 0.133 104.46 ;
     RECT  0.133 103.596 39.395 105.632 ;
     RECT  0.053 173.796 90.755 175.52 ;
     RECT  90.755 173.796 92.389 174.66 ;
     RECT  0 87.396 172.789 88.26 ;
     RECT  0 92.796 172.789 93.66 ;
     RECT  0 98.196 172.885 99.06 ;
     RECT  0 60.396 172.917 61.26 ;
     RECT  172.885 62.72 172.917 62.752 ;
     RECT  172.789 87.232 172.931 88.26 ;
     RECT  172.789 111.872 172.931 111.904 ;
     RECT  172.917 60.396 172.971 62.752 ;
     RECT  172.885 98.196 175.029 99.68 ;
     RECT  174.997 63.232 175.083 63.264 ;
     RECT  175.029 97.472 175.275 99.68 ;
     RECT  92.389 173.796 175.275 175.52 ;
     RECT  172.971 60.396 175.477 61.664 ;
     RECT  175.477 60.396 175.546 62.752 ;
     RECT  175.546 62.72 176.195 62.752 ;
     RECT  172.789 91.904 195.059 93.66 ;
     RECT  193.765 95.36 195.125 95.392 ;
     RECT  195.059 92.032 195.395 93.66 ;
     RECT  175.275 97.792 195.779 99.68 ;
     RECT  172.789 106.176 196.115 106.208 ;
     RECT  196.405 106.048 196.474 106.08 ;
     RECT  195.125 95.36 196.595 96.032 ;
     RECT  195.779 97.792 201.827 99.06 ;
     RECT  201.827 98.196 203.413 99.06 ;
     RECT  196.595 95.616 203.902 96.032 ;
     RECT  203.413 97.792 205.379 99.06 ;
     RECT  203.902 96 205.813 96.032 ;
     RECT  205.813 96 208.931 96.288 ;
     RECT  208.931 96 214.931 96.032 ;
     RECT  196.405 100.8 214.931 100.832 ;
     RECT  0 0.996 216 1.86 ;
     RECT  0 6.396 216 7.26 ;
     RECT  0 11.796 216 12.66 ;
     RECT  0 17.196 216 18.06 ;
     RECT  0 22.596 216 23.46 ;
     RECT  0 27.996 216 28.86 ;
     RECT  0 33.396 216 34.26 ;
     RECT  0 38.796 216 39.66 ;
     RECT  0 44.196 216 45.06 ;
     RECT  0 49.596 216 50.46 ;
     RECT  0 54.996 216 55.86 ;
     RECT  175.546 60.396 216 61.26 ;
     RECT  0 65.796 216 66.66 ;
     RECT  0 71.196 216 72.06 ;
     RECT  0 76.596 216 77.46 ;
     RECT  0 81.996 216 82.86 ;
     RECT  172.931 87.396 216 88.26 ;
     RECT  195.395 92.796 216 93.66 ;
     RECT  205.379 98.196 216 99.06 ;
     RECT  39.395 103.596 216 104.46 ;
     RECT  0 108.996 216 109.86 ;
     RECT  0 114.396 216 115.26 ;
     RECT  0 119.796 216 120.66 ;
     RECT  0 125.196 216 126.06 ;
     RECT  0 130.596 216 131.46 ;
     RECT  0 135.996 216 136.86 ;
     RECT  0 141.396 216 142.26 ;
     RECT  0 146.796 216 147.66 ;
     RECT  0 152.196 216 153.06 ;
     RECT  0 157.596 216 158.46 ;
     RECT  0 162.996 216 163.86 ;
     RECT  0 168.396 216 169.26 ;
     RECT  175.275 173.796 216 174.66 ;
     RECT  0 179.196 216 180.06 ;
     RECT  0 184.596 216 185.46 ;
     RECT  0 189.996 216 190.86 ;
     RECT  0 195.396 216 196.26 ;
     RECT  0 200.796 216 201.66 ;
     RECT  0 206.196 216 207.06 ;
     RECT  0 211.596 216 212.46 ;
    LAYER M7 ;
     RECT  173.656 0.531 173.944 61.621 ;
     RECT  172.928 61.621 173.944 62.763 ;
     RECT  175.488 62.069 175.52 62.763 ;
     RECT  173.656 62.763 173.944 63.221 ;
     RECT  173.656 63.221 175.072 87.221 ;
     RECT  172.8 87.221 175.072 91.947 ;
     RECT  195.256 0.531 195.544 92.021 ;
     RECT  195.136 92.021 195.544 96.043 ;
     RECT  173.656 91.947 175.072 97.461 ;
     RECT  173.656 97.461 175.264 97.515 ;
     RECT  203.84 95.605 203.872 97.835 ;
     RECT  0.856 0.531 1.144 100.789 ;
     RECT  195.256 96.043 195.544 100.789 ;
     RECT  195.256 100.789 196.448 106.091 ;
     RECT  173.656 97.515 173.944 106.165 ;
     RECT  172.8 106.165 173.944 111.915 ;
     RECT  0.064 100.789 1.144 175.531 ;
     RECT  175.232 97.515 175.264 175.531 ;
     RECT  0.856 175.531 1.144 215.469 ;
     RECT  6.256 0.531 6.544 215.469 ;
     RECT  11.656 0.531 11.944 215.469 ;
     RECT  17.056 0.531 17.344 215.469 ;
     RECT  22.456 0.531 22.744 215.469 ;
     RECT  27.856 0.531 28.144 215.469 ;
     RECT  33.256 0.531 33.544 215.469 ;
     RECT  38.656 0.531 38.944 215.469 ;
     RECT  44.056 0.531 44.344 215.469 ;
     RECT  49.456 0.531 49.744 215.469 ;
     RECT  54.856 0.531 55.144 215.469 ;
     RECT  60.256 0.531 60.544 215.469 ;
     RECT  65.656 0.531 65.944 215.469 ;
     RECT  71.056 0.531 71.344 215.469 ;
     RECT  76.456 0.531 76.744 215.469 ;
     RECT  81.856 0.531 82.144 215.469 ;
     RECT  87.256 0.531 87.544 215.469 ;
     RECT  92.656 0.531 92.944 215.469 ;
     RECT  98.056 0.531 98.344 215.469 ;
     RECT  103.456 0.531 103.744 215.469 ;
     RECT  108.856 0.531 109.144 215.469 ;
     RECT  114.256 0.531 114.544 215.469 ;
     RECT  119.656 0.531 119.944 215.469 ;
     RECT  125.056 0.531 125.344 215.469 ;
     RECT  130.456 0.531 130.744 215.469 ;
     RECT  135.856 0.531 136.144 215.469 ;
     RECT  141.256 0.531 141.544 215.469 ;
     RECT  146.656 0.531 146.944 215.469 ;
     RECT  152.056 0.531 152.344 215.469 ;
     RECT  157.456 0.531 157.744 215.469 ;
     RECT  162.856 0.531 163.144 215.469 ;
     RECT  168.256 0.531 168.544 215.469 ;
     RECT  173.656 111.915 173.944 215.469 ;
     RECT  179.056 0.531 179.344 215.469 ;
     RECT  184.456 0.531 184.744 215.469 ;
     RECT  189.856 0.531 190.144 215.469 ;
     RECT  195.256 106.091 195.544 215.469 ;
     RECT  200.656 0.531 200.944 215.469 ;
     RECT  206.056 0.531 206.344 215.469 ;
     RECT  211.456 0.531 211.744 215.469 ;
  END
END dsfd_coll_ck
END LIBRARY
